VERSION 5.8 ;
BUSBITCHARS "[]" ;
DIVIDERCHAR "/" ;
UNITS
    DATABASE MICRONS 1000 ;
END UNITS

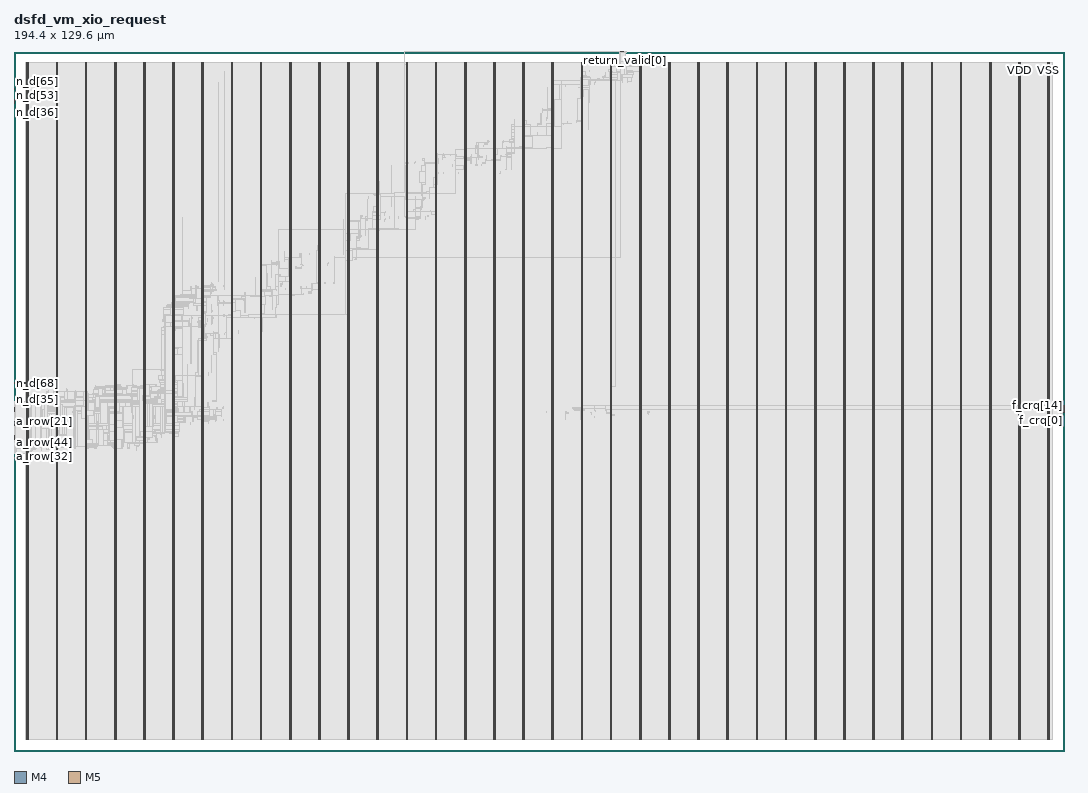
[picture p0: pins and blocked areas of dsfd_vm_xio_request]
MACRO dsfd_vm_xio_request
  FOREIGN dsfd_vm_xio_request 0 0 ;
  CLASS BLOCK ;
  SIZE 194.4 BY 129.6 ;
  PIN a_row[0]
    DIRECTION OUTPUT ;
    USE SIGNAL ;
    PORT
      LAYER M4 ;
        RECT  0 58.992 0.084 59.016 ;
    END
  END a_row[0]
  PIN a_row[10]
    DIRECTION OUTPUT ;
    USE SIGNAL ;
    PORT
      LAYER M4 ;
        RECT  0 59.952 0.084 59.976 ;
    END
  END a_row[10]
  PIN a_row[11]
    DIRECTION OUTPUT ;
    USE SIGNAL ;
    PORT
      LAYER M4 ;
        RECT  0 60.048 0.084 60.072 ;
    END
  END a_row[11]
  PIN a_row[12]
    DIRECTION OUTPUT ;
    USE SIGNAL ;
    PORT
      LAYER M4 ;
        RECT  0 60.144 0.084 60.168 ;
    END
  END a_row[12]
  PIN a_row[13]
    DIRECTION OUTPUT ;
    USE SIGNAL ;
    PORT
      LAYER M4 ;
        RECT  0 60.24 0.084 60.264 ;
    END
  END a_row[13]
  PIN a_row[14]
    DIRECTION OUTPUT ;
    USE SIGNAL ;
    PORT
      LAYER M4 ;
        RECT  0 60.336 0.084 60.36 ;
    END
  END a_row[14]
  PIN a_row[15]
    DIRECTION OUTPUT ;
    USE SIGNAL ;
    PORT
      LAYER M4 ;
        RECT  0 60.432 0.084 60.456 ;
    END
  END a_row[15]
  PIN a_row[16]
    DIRECTION OUTPUT ;
    USE SIGNAL ;
    PORT
      LAYER M4 ;
        RECT  0 60.528 0.084 60.552 ;
    END
  END a_row[16]
  PIN a_row[17]
    DIRECTION OUTPUT ;
    USE SIGNAL ;
    PORT
      LAYER M4 ;
        RECT  0 60.624 0.084 60.648 ;
    END
  END a_row[17]
  PIN a_row[18]
    DIRECTION OUTPUT ;
    USE SIGNAL ;
    PORT
      LAYER M4 ;
        RECT  0 60.72 0.084 60.744 ;
    END
  END a_row[18]
  PIN a_row[19]
    DIRECTION OUTPUT ;
    USE SIGNAL ;
    PORT
      LAYER M4 ;
        RECT  0 60.816 0.084 60.84 ;
    END
  END a_row[19]
  PIN a_row[1]
    DIRECTION OUTPUT ;
    USE SIGNAL ;
    PORT
      LAYER M4 ;
        RECT  0 59.088 0.084 59.112 ;
    END
  END a_row[1]
  PIN a_row[20]
    DIRECTION OUTPUT ;
    USE SIGNAL ;
    PORT
      LAYER M4 ;
        RECT  0 60.912 0.084 60.936 ;
    END
  END a_row[20]
  PIN a_row[21]
    DIRECTION OUTPUT ;
    USE SIGNAL ;
    PORT
      LAYER M4 ;
        RECT  0 61.008 0.084 61.032 ;
    END
  END a_row[21]
  PIN a_row[22]
    DIRECTION OUTPUT ;
    USE SIGNAL ;
    PORT
      LAYER M4 ;
        RECT  0 61.104 0.084 61.128 ;
    END
  END a_row[22]
  PIN a_row[23]
    DIRECTION OUTPUT ;
    USE SIGNAL ;
    PORT
      LAYER M4 ;
        RECT  0 61.2 0.084 61.224 ;
    END
  END a_row[23]
  PIN a_row[24]
    DIRECTION OUTPUT ;
    USE SIGNAL ;
    PORT
      LAYER M4 ;
        RECT  0 61.296 0.084 61.32 ;
    END
  END a_row[24]
  PIN a_row[25]
    DIRECTION OUTPUT ;
    USE SIGNAL ;
    PORT
      LAYER M4 ;
        RECT  0 61.392 0.084 61.416 ;
    END
  END a_row[25]
  PIN a_row[26]
    DIRECTION OUTPUT ;
    USE SIGNAL ;
    PORT
      LAYER M4 ;
        RECT  0 61.488 0.084 61.512 ;
    END
  END a_row[26]
  PIN a_row[27]
    DIRECTION OUTPUT ;
    USE SIGNAL ;
    PORT
      LAYER M4 ;
        RECT  0 61.584 0.084 61.608 ;
    END
  END a_row[27]
  PIN a_row[28]
    DIRECTION OUTPUT ;
    USE SIGNAL ;
    PORT
      LAYER M4 ;
        RECT  0 61.68 0.084 61.704 ;
    END
  END a_row[28]
  PIN a_row[29]
    DIRECTION OUTPUT ;
    USE SIGNAL ;
    PORT
      LAYER M4 ;
        RECT  0 61.776 0.084 61.8 ;
    END
  END a_row[29]
  PIN a_row[2]
    DIRECTION OUTPUT ;
    USE SIGNAL ;
    PORT
      LAYER M4 ;
        RECT  0 59.184 0.084 59.208 ;
    END
  END a_row[2]
  PIN a_row[30]
    DIRECTION OUTPUT ;
    USE SIGNAL ;
    PORT
      LAYER M4 ;
        RECT  0 61.872 0.084 61.896 ;
    END
  END a_row[30]
  PIN a_row[31]
    DIRECTION OUTPUT ;
    USE SIGNAL ;
    PORT
      LAYER M4 ;
        RECT  0 61.968 0.084 61.992 ;
    END
  END a_row[31]
  PIN a_row[32]
    DIRECTION OUTPUT ;
    USE SIGNAL ;
    PORT
      LAYER M4 ;
        RECT  0 55.92 0.084 55.944 ;
    END
  END a_row[32]
  PIN a_row[33]
    DIRECTION OUTPUT ;
    USE SIGNAL ;
    PORT
      LAYER M4 ;
        RECT  0 56.016 0.084 56.04 ;
    END
  END a_row[33]
  PIN a_row[34]
    DIRECTION OUTPUT ;
    USE SIGNAL ;
    PORT
      LAYER M4 ;
        RECT  0 56.112 0.084 56.136 ;
    END
  END a_row[34]
  PIN a_row[35]
    DIRECTION OUTPUT ;
    USE SIGNAL ;
    PORT
      LAYER M4 ;
        RECT  0 56.208 0.084 56.232 ;
    END
  END a_row[35]
  PIN a_row[36]
    DIRECTION OUTPUT ;
    USE SIGNAL ;
    PORT
      LAYER M4 ;
        RECT  0 56.304 0.084 56.328 ;
    END
  END a_row[36]
  PIN a_row[37]
    DIRECTION OUTPUT ;
    USE SIGNAL ;
    PORT
      LAYER M4 ;
        RECT  0 56.4 0.084 56.424 ;
    END
  END a_row[37]
  PIN a_row[38]
    DIRECTION OUTPUT ;
    USE SIGNAL ;
    PORT
      LAYER M4 ;
        RECT  0 56.496 0.084 56.52 ;
    END
  END a_row[38]
  PIN a_row[39]
    DIRECTION OUTPUT ;
    USE SIGNAL ;
    PORT
      LAYER M4 ;
        RECT  0 56.592 0.084 56.616 ;
    END
  END a_row[39]
  PIN a_row[3]
    DIRECTION OUTPUT ;
    USE SIGNAL ;
    PORT
      LAYER M4 ;
        RECT  0 59.28 0.084 59.304 ;
    END
  END a_row[3]
  PIN a_row[40]
    DIRECTION OUTPUT ;
    USE SIGNAL ;
    PORT
      LAYER M4 ;
        RECT  0 56.688 0.084 56.712 ;
    END
  END a_row[40]
  PIN a_row[41]
    DIRECTION OUTPUT ;
    USE SIGNAL ;
    PORT
      LAYER M4 ;
        RECT  0 56.784 0.084 56.808 ;
    END
  END a_row[41]
  PIN a_row[42]
    DIRECTION OUTPUT ;
    USE SIGNAL ;
    PORT
      LAYER M4 ;
        RECT  0 56.88 0.084 56.904 ;
    END
  END a_row[42]
  PIN a_row[43]
    DIRECTION OUTPUT ;
    USE SIGNAL ;
    PORT
      LAYER M4 ;
        RECT  0 56.976 0.084 57 ;
    END
  END a_row[43]
  PIN a_row[44]
    DIRECTION OUTPUT ;
    USE SIGNAL ;
    PORT
      LAYER M4 ;
        RECT  0 57.072 0.084 57.096 ;
    END
  END a_row[44]
  PIN a_row[45]
    DIRECTION OUTPUT ;
    USE SIGNAL ;
    PORT
      LAYER M4 ;
        RECT  0 57.168 0.084 57.192 ;
    END
  END a_row[45]
  PIN a_row[46]
    DIRECTION OUTPUT ;
    USE SIGNAL ;
    PORT
      LAYER M4 ;
        RECT  0 57.264 0.084 57.288 ;
    END
  END a_row[46]
  PIN a_row[47]
    DIRECTION OUTPUT ;
    USE SIGNAL ;
    PORT
      LAYER M4 ;
        RECT  0 57.36 0.084 57.384 ;
    END
  END a_row[47]
  PIN a_row[48]
    DIRECTION OUTPUT ;
    USE SIGNAL ;
    PORT
      LAYER M4 ;
        RECT  0 57.456 0.084 57.48 ;
    END
  END a_row[48]
  PIN a_row[49]
    DIRECTION OUTPUT ;
    USE SIGNAL ;
    PORT
      LAYER M4 ;
        RECT  0 57.552 0.084 57.576 ;
    END
  END a_row[49]
  PIN a_row[4]
    DIRECTION OUTPUT ;
    USE SIGNAL ;
    PORT
      LAYER M4 ;
        RECT  0 59.376 0.084 59.4 ;
    END
  END a_row[4]
  PIN a_row[50]
    DIRECTION OUTPUT ;
    USE SIGNAL ;
    PORT
      LAYER M4 ;
        RECT  0 57.648 0.084 57.672 ;
    END
  END a_row[50]
  PIN a_row[51]
    DIRECTION OUTPUT ;
    USE SIGNAL ;
    PORT
      LAYER M4 ;
        RECT  0 57.744 0.084 57.768 ;
    END
  END a_row[51]
  PIN a_row[52]
    DIRECTION OUTPUT ;
    USE SIGNAL ;
    PORT
      LAYER M4 ;
        RECT  0 57.84 0.084 57.864 ;
    END
  END a_row[52]
  PIN a_row[53]
    DIRECTION OUTPUT ;
    USE SIGNAL ;
    PORT
      LAYER M4 ;
        RECT  0 57.936 0.084 57.96 ;
    END
  END a_row[53]
  PIN a_row[54]
    DIRECTION OUTPUT ;
    USE SIGNAL ;
    PORT
      LAYER M4 ;
        RECT  0 58.032 0.084 58.056 ;
    END
  END a_row[54]
  PIN a_row[55]
    DIRECTION OUTPUT ;
    USE SIGNAL ;
    PORT
      LAYER M4 ;
        RECT  0 58.128 0.084 58.152 ;
    END
  END a_row[55]
  PIN a_row[5]
    DIRECTION OUTPUT ;
    USE SIGNAL ;
    PORT
      LAYER M4 ;
        RECT  0 59.472 0.084 59.496 ;
    END
  END a_row[5]
  PIN a_row[6]
    DIRECTION OUTPUT ;
    USE SIGNAL ;
    PORT
      LAYER M4 ;
        RECT  0 59.568 0.084 59.592 ;
    END
  END a_row[6]
  PIN a_row[7]
    DIRECTION OUTPUT ;
    USE SIGNAL ;
    PORT
      LAYER M4 ;
        RECT  0 59.664 0.084 59.688 ;
    END
  END a_row[7]
  PIN a_row[8]
    DIRECTION OUTPUT ;
    USE SIGNAL ;
    PORT
      LAYER M4 ;
        RECT  0 59.76 0.084 59.784 ;
    END
  END a_row[8]
  PIN a_row[9]
    DIRECTION OUTPUT ;
    USE SIGNAL ;
    PORT
      LAYER M4 ;
        RECT  0 59.856 0.084 59.88 ;
    END
  END a_row[9]
  PIN a_v[0]
    DIRECTION OUTPUT ;
    USE SIGNAL ;
    PORT
      LAYER M4 ;
        RECT  0 58.224 0.084 58.248 ;
    END
  END a_v[0]
  PIN a_v[1]
    DIRECTION OUTPUT ;
    USE SIGNAL ;
    PORT
      LAYER M4 ;
        RECT  0 58.32 0.084 58.344 ;
    END
  END a_v[1]
  PIN a_v[2]
    DIRECTION OUTPUT ;
    USE SIGNAL ;
    PORT
      LAYER M4 ;
        RECT  0 58.416 0.084 58.44 ;
    END
  END a_v[2]
  PIN a_v[3]
    DIRECTION OUTPUT ;
    USE SIGNAL ;
    PORT
      LAYER M4 ;
        RECT  0 58.512 0.084 58.536 ;
    END
  END a_v[3]
  PIN ck
    DIRECTION INPUT ;
    USE SIGNAL ;
    PORT
      LAYER M5 ;
        RECT  112.272 129.516 112.296 129.6 ;
    END
  END ck
  PIN f_crq[0]
    DIRECTION INPUT ;
    USE SIGNAL ;
    PORT
      LAYER M4 ;
        RECT  194.316 62.64 194.4 62.664 ;
    END
  END f_crq[0]
  PIN f_crq[10]
    DIRECTION INPUT ;
    USE SIGNAL ;
    PORT
      LAYER M4 ;
        RECT  194.316 63.6 194.4 63.624 ;
    END
  END f_crq[10]
  PIN f_crq[11]
    DIRECTION INPUT ;
    USE SIGNAL ;
    PORT
      LAYER M4 ;
        RECT  194.316 63.696 194.4 63.72 ;
    END
  END f_crq[11]
  PIN f_crq[12]
    DIRECTION INPUT ;
    USE SIGNAL ;
    PORT
      LAYER M4 ;
        RECT  194.316 63.792 194.4 63.816 ;
    END
  END f_crq[12]
  PIN f_crq[13]
    DIRECTION INPUT ;
    USE SIGNAL ;
    PORT
      LAYER M4 ;
        RECT  194.316 63.888 194.4 63.912 ;
    END
  END f_crq[13]
  PIN f_crq[14]
    DIRECTION INPUT ;
    USE SIGNAL ;
    PORT
      LAYER M4 ;
        RECT  194.316 63.984 194.4 64.008 ;
    END
  END f_crq[14]
  PIN f_crq[1]
    DIRECTION INPUT ;
    USE SIGNAL ;
    PORT
      LAYER M4 ;
        RECT  194.316 62.736 194.4 62.76 ;
    END
  END f_crq[1]
  PIN f_crq[2]
    DIRECTION INPUT ;
    USE SIGNAL ;
    PORT
      LAYER M4 ;
        RECT  194.316 62.832 194.4 62.856 ;
    END
  END f_crq[2]
  PIN f_crq[3]
    DIRECTION INPUT ;
    USE SIGNAL ;
    PORT
      LAYER M4 ;
        RECT  194.316 62.928 194.4 62.952 ;
    END
  END f_crq[3]
  PIN f_crq[4]
    DIRECTION INPUT ;
    USE SIGNAL ;
    PORT
      LAYER M4 ;
        RECT  194.316 63.024 194.4 63.048 ;
    END
  END f_crq[4]
  PIN f_crq[5]
    DIRECTION INPUT ;
    USE SIGNAL ;
    PORT
      LAYER M4 ;
        RECT  194.316 63.12 194.4 63.144 ;
    END
  END f_crq[5]
  PIN f_crq[6]
    DIRECTION INPUT ;
    USE SIGNAL ;
    PORT
      LAYER M4 ;
        RECT  194.316 63.216 194.4 63.24 ;
    END
  END f_crq[6]
  PIN f_crq[7]
    DIRECTION INPUT ;
    USE SIGNAL ;
    PORT
      LAYER M4 ;
        RECT  194.316 63.312 194.4 63.336 ;
    END
  END f_crq[7]
  PIN f_crq[8]
    DIRECTION INPUT ;
    USE SIGNAL ;
    PORT
      LAYER M4 ;
        RECT  194.316 63.408 194.4 63.432 ;
    END
  END f_crq[8]
  PIN f_crq[9]
    DIRECTION INPUT ;
    USE SIGNAL ;
    PORT
      LAYER M4 ;
        RECT  194.316 63.504 194.4 63.528 ;
    END
  END f_crq[9]
  PIN fault
    DIRECTION OUTPUT ;
    USE SIGNAL ;
    PORT
      LAYER M5 ;
        RECT  112.368 129.516 112.392 129.6 ;
    END
  END fault
  PIN n_d[0]
    DIRECTION INPUT ;
    USE SIGNAL ;
    PORT
      LAYER M4 ;
        RECT  0 58.608 0.084 58.632 ;
    END
  END n_d[0]
  PIN n_d[10]
    DIRECTION INPUT ;
    USE SIGNAL ;
    PORT
      LAYER M4 ;
        RECT  0 62.64 0.084 62.664 ;
    END
  END n_d[10]
  PIN n_d[11]
    DIRECTION INPUT ;
    USE SIGNAL ;
    PORT
      LAYER M4 ;
        RECT  0 62.736 0.084 62.76 ;
    END
  END n_d[11]
  PIN n_d[12]
    DIRECTION INPUT ;
    USE SIGNAL ;
    PORT
      LAYER M4 ;
        RECT  0 62.832 0.084 62.856 ;
    END
  END n_d[12]
  PIN n_d[13]
    DIRECTION INPUT ;
    USE SIGNAL ;
    PORT
      LAYER M4 ;
        RECT  0 62.928 0.084 62.952 ;
    END
  END n_d[13]
  PIN n_d[14]
    DIRECTION INPUT ;
    USE SIGNAL ;
    PORT
      LAYER M4 ;
        RECT  0 63.024 0.084 63.048 ;
    END
  END n_d[14]
  PIN n_d[15]
    DIRECTION INPUT ;
    USE SIGNAL ;
    PORT
      LAYER M4 ;
        RECT  0 63.12 0.084 63.144 ;
    END
  END n_d[15]
  PIN n_d[16]
    DIRECTION INPUT ;
    USE SIGNAL ;
    PORT
      LAYER M4 ;
        RECT  0 63.216 0.084 63.24 ;
    END
  END n_d[16]
  PIN n_d[17]
    DIRECTION INPUT ;
    USE SIGNAL ;
    PORT
      LAYER M4 ;
        RECT  0 63.312 0.084 63.336 ;
    END
  END n_d[17]
  PIN n_d[18]
    DIRECTION INPUT ;
    USE SIGNAL ;
    PORT
      LAYER M4 ;
        RECT  0 63.408 0.084 63.432 ;
    END
  END n_d[18]
  PIN n_d[19]
    DIRECTION INPUT ;
    USE SIGNAL ;
    PORT
      LAYER M4 ;
        RECT  0 63.504 0.084 63.528 ;
    END
  END n_d[19]
  PIN n_d[1]
    DIRECTION INPUT ;
    USE SIGNAL ;
    PORT
      LAYER M4 ;
        RECT  0 58.704 0.084 58.728 ;
    END
  END n_d[1]
  PIN n_d[20]
    DIRECTION INPUT ;
    USE SIGNAL ;
    PORT
      LAYER M4 ;
        RECT  0 63.6 0.084 63.624 ;
    END
  END n_d[20]
  PIN n_d[21]
    DIRECTION INPUT ;
    USE SIGNAL ;
    PORT
      LAYER M4 ;
        RECT  0 63.696 0.084 63.72 ;
    END
  END n_d[21]
  PIN n_d[22]
    DIRECTION INPUT ;
    USE SIGNAL ;
    PORT
      LAYER M4 ;
        RECT  0 63.792 0.084 63.816 ;
    END
  END n_d[22]
  PIN n_d[23]
    DIRECTION INPUT ;
    USE SIGNAL ;
    PORT
      LAYER M4 ;
        RECT  0 63.888 0.084 63.912 ;
    END
  END n_d[23]
  PIN n_d[24]
    DIRECTION INPUT ;
    USE SIGNAL ;
    PORT
      LAYER M4 ;
        RECT  0 63.984 0.084 64.008 ;
    END
  END n_d[24]
  PIN n_d[25]
    DIRECTION INPUT ;
    USE SIGNAL ;
    PORT
      LAYER M4 ;
        RECT  0 64.08 0.084 64.104 ;
    END
  END n_d[25]
  PIN n_d[26]
    DIRECTION INPUT ;
    USE SIGNAL ;
    PORT
      LAYER M4 ;
        RECT  0 64.176 0.084 64.2 ;
    END
  END n_d[26]
  PIN n_d[27]
    DIRECTION INPUT ;
    USE SIGNAL ;
    PORT
      LAYER M4 ;
        RECT  0 64.272 0.084 64.296 ;
    END
  END n_d[27]
  PIN n_d[28]
    DIRECTION INPUT ;
    USE SIGNAL ;
    PORT
      LAYER M4 ;
        RECT  0 64.368 0.084 64.392 ;
    END
  END n_d[28]
  PIN n_d[29]
    DIRECTION INPUT ;
    USE SIGNAL ;
    PORT
      LAYER M4 ;
        RECT  0 64.464 0.084 64.488 ;
    END
  END n_d[29]
  PIN n_d[2]
    DIRECTION INPUT ;
    USE SIGNAL ;
    PORT
      LAYER M4 ;
        RECT  0 58.8 0.084 58.824 ;
    END
  END n_d[2]
  PIN n_d[30]
    DIRECTION INPUT ;
    USE SIGNAL ;
    PORT
      LAYER M4 ;
        RECT  0 64.56 0.084 64.584 ;
    END
  END n_d[30]
  PIN n_d[31]
    DIRECTION INPUT ;
    USE SIGNAL ;
    PORT
      LAYER M4 ;
        RECT  0 64.656 0.084 64.68 ;
    END
  END n_d[31]
  PIN n_d[32]
    DIRECTION INPUT ;
    USE SIGNAL ;
    PORT
      LAYER M4 ;
        RECT  0 64.752 0.084 64.776 ;
    END
  END n_d[32]
  PIN n_d[33]
    DIRECTION INPUT ;
    USE SIGNAL ;
    PORT
      LAYER M4 ;
        RECT  0 64.848 0.084 64.872 ;
    END
  END n_d[33]
  PIN n_d[34]
    DIRECTION INPUT ;
    USE SIGNAL ;
    PORT
      LAYER M4 ;
        RECT  0 64.944 0.084 64.968 ;
    END
  END n_d[34]
  PIN n_d[35]
    DIRECTION INPUT ;
    USE SIGNAL ;
    PORT
      LAYER M4 ;
        RECT  0 65.04 0.084 65.064 ;
    END
  END n_d[35]
  PIN n_d[36]
    DIRECTION INPUT ;
    USE SIGNAL ;
    PORT
      LAYER M4 ;
        RECT  0 119.664 0.084 119.688 ;
    END
  END n_d[36]
  PIN n_d[37]
    DIRECTION INPUT ;
    USE SIGNAL ;
    PORT
      LAYER M4 ;
        RECT  0 119.76 0.084 119.784 ;
    END
  END n_d[37]
  PIN n_d[38]
    DIRECTION INPUT ;
    USE SIGNAL ;
    PORT
      LAYER M4 ;
        RECT  0 119.856 0.084 119.88 ;
    END
  END n_d[38]
  PIN n_d[39]
    DIRECTION INPUT ;
    USE SIGNAL ;
    PORT
      LAYER M4 ;
        RECT  0 119.952 0.084 119.976 ;
    END
  END n_d[39]
  PIN n_d[3]
    DIRECTION INPUT ;
    USE SIGNAL ;
    PORT
      LAYER M4 ;
        RECT  0 58.896 0.084 58.92 ;
    END
  END n_d[3]
  PIN n_d[40]
    DIRECTION INPUT ;
    USE SIGNAL ;
    PORT
      LAYER M4 ;
        RECT  0 120.048 0.084 120.072 ;
    END
  END n_d[40]
  PIN n_d[41]
    DIRECTION INPUT ;
    USE SIGNAL ;
    PORT
      LAYER M4 ;
        RECT  0 120.144 0.084 120.168 ;
    END
  END n_d[41]
  PIN n_d[42]
    DIRECTION INPUT ;
    USE SIGNAL ;
    PORT
      LAYER M4 ;
        RECT  0 120.24 0.084 120.264 ;
    END
  END n_d[42]
  PIN n_d[43]
    DIRECTION INPUT ;
    USE SIGNAL ;
    PORT
      LAYER M4 ;
        RECT  0 120.336 0.084 120.36 ;
    END
  END n_d[43]
  PIN n_d[44]
    DIRECTION INPUT ;
    USE SIGNAL ;
    PORT
      LAYER M4 ;
        RECT  0 120.432 0.084 120.456 ;
    END
  END n_d[44]
  PIN n_d[45]
    DIRECTION INPUT ;
    USE SIGNAL ;
    PORT
      LAYER M4 ;
        RECT  0 120.528 0.084 120.552 ;
    END
  END n_d[45]
  PIN n_d[46]
    DIRECTION INPUT ;
    USE SIGNAL ;
    PORT
      LAYER M4 ;
        RECT  0 120.624 0.084 120.648 ;
    END
  END n_d[46]
  PIN n_d[47]
    DIRECTION INPUT ;
    USE SIGNAL ;
    PORT
      LAYER M4 ;
        RECT  0 120.72 0.084 120.744 ;
    END
  END n_d[47]
  PIN n_d[48]
    DIRECTION INPUT ;
    USE SIGNAL ;
    PORT
      LAYER M4 ;
        RECT  0 120.816 0.084 120.84 ;
    END
  END n_d[48]
  PIN n_d[49]
    DIRECTION INPUT ;
    USE SIGNAL ;
    PORT
      LAYER M4 ;
        RECT  0 120.912 0.084 120.936 ;
    END
  END n_d[49]
  PIN n_d[4]
    DIRECTION INPUT ;
    USE SIGNAL ;
    PORT
      LAYER M4 ;
        RECT  0 62.064 0.084 62.088 ;
    END
  END n_d[4]
  PIN n_d[50]
    DIRECTION INPUT ;
    USE SIGNAL ;
    PORT
      LAYER M4 ;
        RECT  0 121.008 0.084 121.032 ;
    END
  END n_d[50]
  PIN n_d[51]
    DIRECTION INPUT ;
    USE SIGNAL ;
    PORT
      LAYER M4 ;
        RECT  0 121.104 0.084 121.128 ;
    END
  END n_d[51]
  PIN n_d[52]
    DIRECTION INPUT ;
    USE SIGNAL ;
    PORT
      LAYER M4 ;
        RECT  0 121.2 0.084 121.224 ;
    END
  END n_d[52]
  PIN n_d[53]
    DIRECTION INPUT ;
    USE SIGNAL ;
    PORT
      LAYER M4 ;
        RECT  0 121.296 0.084 121.32 ;
    END
  END n_d[53]
  PIN n_d[54]
    DIRECTION INPUT ;
    USE SIGNAL ;
    PORT
      LAYER M4 ;
        RECT  0 121.392 0.084 121.416 ;
    END
  END n_d[54]
  PIN n_d[55]
    DIRECTION INPUT ;
    USE SIGNAL ;
    PORT
      LAYER M4 ;
        RECT  0 121.488 0.084 121.512 ;
    END
  END n_d[55]
  PIN n_d[56]
    DIRECTION INPUT ;
    USE SIGNAL ;
    PORT
      LAYER M4 ;
        RECT  0 121.584 0.084 121.608 ;
    END
  END n_d[56]
  PIN n_d[57]
    DIRECTION INPUT ;
    USE SIGNAL ;
    PORT
      LAYER M4 ;
        RECT  0 121.68 0.084 121.704 ;
    END
  END n_d[57]
  PIN n_d[58]
    DIRECTION INPUT ;
    USE SIGNAL ;
    PORT
      LAYER M4 ;
        RECT  0 121.776 0.084 121.8 ;
    END
  END n_d[58]
  PIN n_d[59]
    DIRECTION INPUT ;
    USE SIGNAL ;
    PORT
      LAYER M4 ;
        RECT  0 121.872 0.084 121.896 ;
    END
  END n_d[59]
  PIN n_d[5]
    DIRECTION INPUT ;
    USE SIGNAL ;
    PORT
      LAYER M4 ;
        RECT  0 62.16 0.084 62.184 ;
    END
  END n_d[5]
  PIN n_d[60]
    DIRECTION INPUT ;
    USE SIGNAL ;
    PORT
      LAYER M4 ;
        RECT  0 121.968 0.084 121.992 ;
    END
  END n_d[60]
  PIN n_d[61]
    DIRECTION INPUT ;
    USE SIGNAL ;
    PORT
      LAYER M4 ;
        RECT  0 122.064 0.084 122.088 ;
    END
  END n_d[61]
  PIN n_d[62]
    DIRECTION INPUT ;
    USE SIGNAL ;
    PORT
      LAYER M4 ;
        RECT  0 122.16 0.084 122.184 ;
    END
  END n_d[62]
  PIN n_d[63]
    DIRECTION INPUT ;
    USE SIGNAL ;
    PORT
      LAYER M4 ;
        RECT  0 122.256 0.084 122.28 ;
    END
  END n_d[63]
  PIN n_d[64]
    DIRECTION INPUT ;
    USE SIGNAL ;
    PORT
      LAYER M4 ;
        RECT  0 122.352 0.084 122.376 ;
    END
  END n_d[64]
  PIN n_d[65]
    DIRECTION INPUT ;
    USE SIGNAL ;
    PORT
      LAYER M4 ;
        RECT  0 122.448 0.084 122.472 ;
    END
  END n_d[65]
  PIN n_d[66]
    DIRECTION INPUT ;
    USE SIGNAL ;
    PORT
      LAYER M4 ;
        RECT  0 122.544 0.084 122.568 ;
    END
  END n_d[66]
  PIN n_d[67]
    DIRECTION INPUT ;
    USE SIGNAL ;
    PORT
      LAYER M4 ;
        RECT  0 122.64 0.084 122.664 ;
    END
  END n_d[67]
  PIN n_d[68]
    DIRECTION INPUT ;
    USE SIGNAL ;
    PORT
      LAYER M4 ;
        RECT  0 66.576 0.084 66.6 ;
    END
  END n_d[68]
  PIN n_d[69]
    DIRECTION INPUT ;
    USE SIGNAL ;
    PORT
      LAYER M4 ;
        RECT  0 66.672 0.084 66.696 ;
    END
  END n_d[69]
  PIN n_d[6]
    DIRECTION INPUT ;
    USE SIGNAL ;
    PORT
      LAYER M4 ;
        RECT  0 62.256 0.084 62.28 ;
    END
  END n_d[6]
  PIN n_d[70]
    DIRECTION INPUT ;
    USE SIGNAL ;
    PORT
      LAYER M4 ;
        RECT  0 66.768 0.084 66.792 ;
    END
  END n_d[70]
  PIN n_d[71]
    DIRECTION INPUT ;
    USE SIGNAL ;
    PORT
      LAYER M4 ;
        RECT  0 66.864 0.084 66.888 ;
    END
  END n_d[71]
  PIN n_d[72]
    DIRECTION INPUT ;
    USE SIGNAL ;
    PORT
      LAYER M4 ;
        RECT  0 66.96 0.084 66.984 ;
    END
  END n_d[72]
  PIN n_d[73]
    DIRECTION INPUT ;
    USE SIGNAL ;
    PORT
      LAYER M4 ;
        RECT  0 67.056 0.084 67.08 ;
    END
  END n_d[73]
  PIN n_d[74]
    DIRECTION INPUT ;
    USE SIGNAL ;
    PORT
      LAYER M4 ;
        RECT  0 67.152 0.084 67.176 ;
    END
  END n_d[74]
  PIN n_d[75]
    DIRECTION INPUT ;
    USE SIGNAL ;
    PORT
      LAYER M4 ;
        RECT  0 67.248 0.084 67.272 ;
    END
  END n_d[75]
  PIN n_d[76]
    DIRECTION INPUT ;
    USE SIGNAL ;
    PORT
      LAYER M4 ;
        RECT  0 67.344 0.084 67.368 ;
    END
  END n_d[76]
  PIN n_d[77]
    DIRECTION INPUT ;
    USE SIGNAL ;
    PORT
      LAYER M4 ;
        RECT  0 67.44 0.084 67.464 ;
    END
  END n_d[77]
  PIN n_d[78]
    DIRECTION INPUT ;
    USE SIGNAL ;
    PORT
      LAYER M4 ;
        RECT  0 67.536 0.084 67.56 ;
    END
  END n_d[78]
  PIN n_d[79]
    DIRECTION INPUT ;
    USE SIGNAL ;
    PORT
      LAYER M4 ;
        RECT  0 67.632 0.084 67.656 ;
    END
  END n_d[79]
  PIN n_d[7]
    DIRECTION INPUT ;
    USE SIGNAL ;
    PORT
      LAYER M4 ;
        RECT  0 62.352 0.084 62.376 ;
    END
  END n_d[7]
  PIN n_d[80]
    DIRECTION INPUT ;
    USE SIGNAL ;
    PORT
      LAYER M4 ;
        RECT  0 67.728 0.084 67.752 ;
    END
  END n_d[80]
  PIN n_d[81]
    DIRECTION INPUT ;
    USE SIGNAL ;
    PORT
      LAYER M4 ;
        RECT  0 67.824 0.084 67.848 ;
    END
  END n_d[81]
  PIN n_d[82]
    DIRECTION INPUT ;
    USE SIGNAL ;
    PORT
      LAYER M4 ;
        RECT  0 67.92 0.084 67.944 ;
    END
  END n_d[82]
  PIN n_d[83]
    DIRECTION INPUT ;
    USE SIGNAL ;
    PORT
      LAYER M4 ;
        RECT  0 68.016 0.084 68.04 ;
    END
  END n_d[83]
  PIN n_d[8]
    DIRECTION INPUT ;
    USE SIGNAL ;
    PORT
      LAYER M4 ;
        RECT  0 62.448 0.084 62.472 ;
    END
  END n_d[8]
  PIN n_d[9]
    DIRECTION INPUT ;
    USE SIGNAL ;
    PORT
      LAYER M4 ;
        RECT  0 62.544 0.084 62.568 ;
    END
  END n_d[9]
  PIN n_v
    DIRECTION INPUT ;
    USE SIGNAL ;
    PORT
      LAYER M4 ;
        RECT  0 68.112 0.084 68.136 ;
    END
    PORT
      LAYER M4 ;
        RECT  0.06 68.112 2.408 68.136 ;
    END
  END n_v
  PIN return_lane[0]
    DIRECTION OUTPUT ;
    USE SIGNAL ;
    PORT
      LAYER M5 ;
        RECT  112.464 129.516 112.488 129.6 ;
    END
  END return_lane[0]
  PIN return_lane[1]
    DIRECTION OUTPUT ;
    USE SIGNAL ;
    PORT
      LAYER M5 ;
        RECT  112.56 129.516 112.584 129.6 ;
    END
  END return_lane[1]
  PIN return_lane[2]
    DIRECTION OUTPUT ;
    USE SIGNAL ;
    PORT
      LAYER M5 ;
        RECT  112.656 129.516 112.68 129.6 ;
    END
  END return_lane[2]
  PIN return_lane[3]
    DIRECTION OUTPUT ;
    USE SIGNAL ;
    PORT
      LAYER M5 ;
        RECT  112.752 129.516 112.776 129.6 ;
    END
  END return_lane[3]
  PIN return_lane[4]
    DIRECTION OUTPUT ;
    USE SIGNAL ;
    PORT
      LAYER M5 ;
        RECT  112.848 129.516 112.872 129.6 ;
    END
  END return_lane[4]
  PIN return_lane[5]
    DIRECTION OUTPUT ;
    USE SIGNAL ;
    PORT
      LAYER M5 ;
        RECT  112.944 129.516 112.968 129.6 ;
    END
  END return_lane[5]
  PIN return_valid[0]
    DIRECTION OUTPUT ;
    USE SIGNAL ;
    PORT
      LAYER M5 ;
        RECT  113.04 129.516 113.064 129.6 ;
    END
  END return_valid[0]
  PIN return_valid[1]
    DIRECTION OUTPUT ;
    USE SIGNAL ;
    PORT
      LAYER M5 ;
        RECT  113.136 129.516 113.16 129.6 ;
    END
  END return_valid[1]
  PIN return_valid[2]
    DIRECTION OUTPUT ;
    USE SIGNAL ;
    PORT
      LAYER M5 ;
        RECT  113.232 129.516 113.256 129.6 ;
    END
  END return_valid[2]
  PIN rst_n
    DIRECTION INPUT ;
    USE SIGNAL ;
    PORT
      LAYER M5 ;
        RECT  113.328 129.516 113.352 129.6 ;
    END
  END rst_n
  PIN VDD
    DIRECTION INOUT ;
    USE POWER ;
    PORT
      LAYER M5 ;
        RECT  191.592 2.151 191.712 127.449 ;
        RECT  186.192 2.151 186.312 127.449 ;
        RECT  180.792 2.151 180.912 127.449 ;
        RECT  175.392 2.151 175.512 127.449 ;
        RECT  169.992 2.151 170.112 127.449 ;
        RECT  164.592 2.151 164.712 127.449 ;
        RECT  159.192 2.151 159.312 127.449 ;
        RECT  153.792 2.151 153.912 127.449 ;
        RECT  148.392 2.151 148.512 127.449 ;
        RECT  142.992 2.151 143.112 127.449 ;
        RECT  137.592 2.151 137.712 127.449 ;
        RECT  132.192 2.151 132.312 127.449 ;
        RECT  126.792 2.151 126.912 127.449 ;
        RECT  121.392 2.151 121.512 127.449 ;
        RECT  115.992 2.151 116.112 127.449 ;
        RECT  110.592 2.151 110.712 127.449 ;
        RECT  105.192 2.151 105.312 127.449 ;
        RECT  99.792 2.151 99.912 127.449 ;
        RECT  94.392 2.151 94.512 127.449 ;
        RECT  88.992 2.151 89.112 127.449 ;
        RECT  83.592 2.151 83.712 127.449 ;
        RECT  78.192 2.151 78.312 127.449 ;
        RECT  72.792 2.151 72.912 127.449 ;
        RECT  67.392 2.151 67.512 127.449 ;
        RECT  61.992 2.151 62.112 127.449 ;
        RECT  56.592 2.151 56.712 127.449 ;
        RECT  51.192 2.151 51.312 127.449 ;
        RECT  45.792 2.151 45.912 127.449 ;
        RECT  40.392 2.151 40.512 127.449 ;
        RECT  34.992 2.151 35.112 127.449 ;
        RECT  29.592 2.151 29.712 127.449 ;
        RECT  24.192 2.151 24.312 127.449 ;
        RECT  18.792 2.151 18.912 127.449 ;
        RECT  13.392 2.151 13.512 127.449 ;
        RECT  7.992 2.151 8.112 127.449 ;
        RECT  2.592 2.151 2.712 127.449 ;
    END
  END VDD
  PIN VSS
    DIRECTION INOUT ;
    USE GROUND ;
    PORT
      LAYER M5 ;
        RECT  191.4 2.137 191.52 127.463 ;
        RECT  186 2.137 186.12 127.463 ;
        RECT  180.6 2.137 180.72 127.463 ;
        RECT  175.2 2.137 175.32 127.463 ;
        RECT  169.8 2.137 169.92 127.463 ;
        RECT  164.4 2.137 164.52 127.463 ;
        RECT  159 2.137 159.12 127.463 ;
        RECT  153.6 2.137 153.72 127.463 ;
        RECT  148.2 2.137 148.32 127.463 ;
        RECT  142.8 2.137 142.92 127.463 ;
        RECT  137.4 2.137 137.52 127.463 ;
        RECT  132 2.137 132.12 127.463 ;
        RECT  126.6 2.137 126.72 127.463 ;
        RECT  121.2 2.137 121.32 127.463 ;
        RECT  115.8 2.137 115.92 127.463 ;
        RECT  110.4 2.137 110.52 127.463 ;
        RECT  105 2.137 105.12 127.463 ;
        RECT  99.6 2.137 99.72 127.463 ;
        RECT  94.2 2.137 94.32 127.463 ;
        RECT  88.8 2.137 88.92 127.463 ;
        RECT  83.4 2.137 83.52 127.463 ;
        RECT  78 2.137 78.12 127.463 ;
        RECT  72.6 2.137 72.72 127.463 ;
        RECT  67.2 2.137 67.32 127.463 ;
        RECT  61.8 2.137 61.92 127.463 ;
        RECT  56.4 2.137 56.52 127.463 ;
        RECT  51 2.137 51.12 127.463 ;
        RECT  45.6 2.137 45.72 127.463 ;
        RECT  40.2 2.137 40.32 127.463 ;
        RECT  34.8 2.137 34.92 127.463 ;
        RECT  29.4 2.137 29.52 127.463 ;
        RECT  24 2.137 24.12 127.463 ;
        RECT  18.6 2.137 18.72 127.463 ;
        RECT  13.2 2.137 13.32 127.463 ;
        RECT  7.8 2.137 7.92 127.463 ;
        RECT  2.4 2.137 2.52 127.463 ;
    END
  END VSS
  # OT_OBS_CLOSED layer=M5 d_um=1.536 added=39
  OBS
    LAYER RVTN ;
     RECT  2.16 2.16 192.24 2.295 ;
     RECT  2.16 2.565 192.24 2.835 ;
     RECT  2.16 3.105 192.24 3.375 ;
     RECT  2.16 3.645 192.24 3.915 ;
     RECT  2.16 4.185 192.24 4.455 ;
     RECT  2.16 4.725 192.24 4.995 ;
     RECT  2.16 5.265 192.24 5.535 ;
     RECT  2.16 5.805 192.24 6.075 ;
     RECT  2.16 6.345 192.24 6.615 ;
     RECT  2.16 6.885 192.24 7.155 ;
     RECT  2.16 7.425 192.24 7.695 ;
     RECT  2.16 7.965 192.24 8.235 ;
     RECT  2.16 8.505 192.24 8.775 ;
     RECT  2.16 9.045 192.24 9.315 ;
     RECT  2.16 9.585 192.24 9.855 ;
     RECT  2.16 10.125 192.24 10.395 ;
     RECT  2.16 10.665 192.24 10.935 ;
     RECT  2.16 11.205 192.24 11.475 ;
     RECT  2.16 11.745 192.24 12.015 ;
     RECT  2.16 12.285 192.24 12.555 ;
     RECT  2.16 12.825 192.24 13.095 ;
     RECT  2.16 13.365 192.24 13.635 ;
     RECT  2.16 13.905 192.24 14.175 ;
     RECT  2.16 14.445 192.24 14.715 ;
     RECT  2.16 14.985 192.24 15.255 ;
     RECT  2.16 15.525 192.24 15.795 ;
     RECT  2.16 16.065 192.24 16.335 ;
     RECT  2.16 16.605 192.24 16.875 ;
     RECT  2.16 17.145 192.24 17.415 ;
     RECT  2.16 17.685 192.24 17.955 ;
     RECT  2.16 18.225 192.24 18.495 ;
     RECT  2.16 18.765 192.24 19.035 ;
     RECT  2.16 19.305 192.24 19.575 ;
     RECT  2.16 19.845 192.24 20.115 ;
     RECT  2.16 20.385 192.24 20.655 ;
     RECT  2.16 20.925 192.24 21.195 ;
     RECT  2.16 21.465 192.24 21.735 ;
     RECT  2.16 22.005 192.24 22.275 ;
     RECT  2.16 22.545 192.24 22.815 ;
     RECT  2.16 23.085 192.24 23.355 ;
     RECT  2.16 23.625 192.24 23.895 ;
     RECT  2.16 24.165 192.24 24.435 ;
     RECT  2.16 24.705 192.24 24.975 ;
     RECT  2.16 25.245 192.24 25.515 ;
     RECT  2.16 25.785 192.24 26.055 ;
     RECT  2.16 26.325 192.24 26.595 ;
     RECT  2.16 26.865 192.24 27.135 ;
     RECT  2.16 27.405 192.24 27.675 ;
     RECT  2.16 27.945 192.24 28.215 ;
     RECT  2.16 28.485 192.24 28.755 ;
     RECT  2.16 29.025 192.24 29.295 ;
     RECT  2.16 29.565 192.24 29.835 ;
     RECT  2.16 30.105 192.24 30.375 ;
     RECT  2.16 30.645 192.24 30.915 ;
     RECT  2.16 31.185 192.24 31.455 ;
     RECT  2.16 31.725 192.24 31.995 ;
     RECT  2.16 32.265 192.24 32.535 ;
     RECT  2.16 32.805 192.24 33.075 ;
     RECT  2.16 33.345 192.24 33.615 ;
     RECT  2.16 33.885 192.24 34.155 ;
     RECT  2.16 34.425 192.24 34.695 ;
     RECT  2.16 34.965 192.24 35.235 ;
     RECT  2.16 35.505 192.24 35.775 ;
     RECT  2.16 36.045 192.24 36.315 ;
     RECT  2.16 36.585 192.24 36.855 ;
     RECT  2.16 37.125 192.24 37.395 ;
     RECT  2.16 37.665 192.24 37.935 ;
     RECT  2.16 38.205 192.24 38.475 ;
     RECT  2.16 38.745 192.24 39.015 ;
     RECT  2.16 39.285 192.24 39.555 ;
     RECT  2.16 39.825 192.24 40.095 ;
     RECT  2.16 40.365 192.24 40.635 ;
     RECT  2.16 40.905 192.24 41.175 ;
     RECT  2.16 41.445 192.24 41.715 ;
     RECT  2.16 41.985 192.24 42.255 ;
     RECT  2.16 42.525 192.24 42.795 ;
     RECT  2.16 43.065 192.24 43.335 ;
     RECT  2.16 43.605 192.24 43.875 ;
     RECT  2.16 44.145 192.24 44.415 ;
     RECT  2.16 44.685 192.24 44.955 ;
     RECT  2.16 45.225 192.24 45.495 ;
     RECT  2.16 45.765 192.24 46.035 ;
     RECT  2.16 46.305 192.24 46.575 ;
     RECT  2.16 46.845 192.24 47.115 ;
     RECT  2.16 47.385 192.24 47.655 ;
     RECT  2.16 47.925 192.24 48.195 ;
     RECT  2.16 48.465 192.24 48.735 ;
     RECT  2.16 49.005 192.24 49.275 ;
     RECT  2.16 49.545 192.24 49.815 ;
     RECT  2.16 50.085 192.24 50.355 ;
     RECT  2.16 50.625 192.24 50.895 ;
     RECT  2.16 51.165 192.24 51.435 ;
     RECT  2.16 51.705 192.24 51.975 ;
     RECT  2.16 52.245 192.24 52.515 ;
     RECT  2.16 52.785 192.24 53.055 ;
     RECT  2.16 53.325 192.24 53.595 ;
     RECT  2.16 53.865 192.24 54.135 ;
     RECT  2.16 54.405 192.24 54.675 ;
     RECT  2.16 54.945 192.24 55.215 ;
     RECT  2.16 55.485 192.24 55.755 ;
     RECT  2.16 56.025 192.24 56.295 ;
     RECT  2.16 56.565 192.24 56.835 ;
     RECT  2.16 57.105 192.24 57.375 ;
     RECT  2.16 57.645 192.24 57.915 ;
     RECT  2.16 58.185 192.24 58.455 ;
     RECT  2.16 58.725 192.24 58.995 ;
     RECT  2.16 59.265 192.24 59.535 ;
     RECT  2.16 59.805 192.24 60.075 ;
     RECT  2.16 60.345 192.24 60.615 ;
     RECT  2.16 60.885 192.24 61.155 ;
     RECT  2.16 61.425 192.24 61.695 ;
     RECT  2.16 61.965 192.24 62.235 ;
     RECT  2.16 62.505 192.24 62.775 ;
     RECT  2.16 63.045 192.24 63.315 ;
     RECT  2.16 63.585 192.24 63.855 ;
     RECT  2.16 64.125 192.24 64.395 ;
     RECT  2.16 64.665 192.24 64.935 ;
     RECT  2.16 65.205 192.24 65.475 ;
     RECT  2.16 65.745 192.24 66.015 ;
     RECT  2.16 66.285 192.24 66.555 ;
     RECT  2.16 66.825 192.24 67.095 ;
     RECT  2.16 67.365 192.24 67.635 ;
     RECT  2.16 67.905 192.24 68.175 ;
     RECT  2.16 68.445 192.24 68.715 ;
     RECT  2.16 68.985 192.24 69.255 ;
     RECT  2.16 69.525 192.24 69.795 ;
     RECT  2.16 70.065 192.24 70.335 ;
     RECT  2.16 70.605 192.24 70.875 ;
     RECT  2.16 71.145 192.24 71.415 ;
     RECT  2.16 71.685 192.24 71.955 ;
     RECT  2.16 72.225 192.24 72.495 ;
     RECT  2.16 72.765 192.24 73.035 ;
     RECT  2.16 73.305 192.24 73.575 ;
     RECT  2.16 73.845 192.24 74.115 ;
     RECT  2.16 74.385 192.24 74.655 ;
     RECT  2.16 74.925 192.24 75.195 ;
     RECT  2.16 75.465 192.24 75.735 ;
     RECT  2.16 76.005 192.24 76.275 ;
     RECT  2.16 76.545 192.24 76.815 ;
     RECT  2.16 77.085 192.24 77.355 ;
     RECT  2.16 77.625 192.24 77.895 ;
     RECT  2.16 78.165 192.24 78.435 ;
     RECT  2.16 78.705 192.24 78.975 ;
     RECT  2.16 79.245 192.24 79.515 ;
     RECT  2.16 79.785 192.24 80.055 ;
     RECT  2.16 80.325 192.24 80.595 ;
     RECT  2.16 80.865 192.24 81.135 ;
     RECT  2.16 81.405 192.24 81.675 ;
     RECT  2.16 81.945 192.24 82.215 ;
     RECT  2.16 82.485 192.24 82.755 ;
     RECT  2.16 83.025 192.24 83.295 ;
     RECT  2.16 83.565 192.24 83.835 ;
     RECT  2.16 84.105 192.24 84.375 ;
     RECT  2.16 84.645 192.24 84.915 ;
     RECT  2.16 85.185 192.24 85.455 ;
     RECT  2.16 85.725 192.24 85.995 ;
     RECT  2.16 86.265 192.24 86.535 ;
     RECT  2.16 86.805 192.24 87.075 ;
     RECT  2.16 87.345 192.24 87.615 ;
     RECT  2.16 87.885 192.24 88.155 ;
     RECT  2.16 88.425 192.24 88.695 ;
     RECT  2.16 88.965 192.24 89.235 ;
     RECT  2.16 89.505 192.24 89.775 ;
     RECT  2.16 90.045 192.24 90.315 ;
     RECT  2.16 90.585 192.24 90.855 ;
     RECT  2.16 91.125 192.24 91.395 ;
     RECT  2.16 91.665 192.24 91.935 ;
     RECT  2.16 92.205 192.24 92.475 ;
     RECT  2.16 92.745 192.24 93.015 ;
     RECT  2.16 93.285 192.24 93.555 ;
     RECT  2.16 93.825 192.24 94.095 ;
     RECT  2.16 94.365 192.24 94.635 ;
     RECT  2.16 94.905 192.24 95.175 ;
     RECT  2.16 95.445 192.24 95.715 ;
     RECT  2.16 95.985 192.24 96.255 ;
     RECT  2.16 96.525 192.24 96.795 ;
     RECT  2.16 97.065 192.24 97.335 ;
     RECT  2.16 97.605 192.24 97.875 ;
     RECT  2.16 98.145 192.24 98.415 ;
     RECT  2.16 98.685 192.24 98.955 ;
     RECT  2.16 99.225 192.24 99.495 ;
     RECT  2.16 99.765 192.24 100.035 ;
     RECT  2.16 100.305 192.24 100.575 ;
     RECT  2.16 100.845 192.24 101.115 ;
     RECT  2.16 101.385 192.24 101.655 ;
     RECT  2.16 101.925 192.24 102.195 ;
     RECT  2.16 102.465 192.24 102.735 ;
     RECT  2.16 103.005 192.24 103.275 ;
     RECT  2.16 103.545 192.24 103.815 ;
     RECT  2.16 104.085 192.24 104.355 ;
     RECT  2.16 104.625 192.24 104.895 ;
     RECT  2.16 105.165 192.24 105.435 ;
     RECT  2.16 105.705 192.24 105.975 ;
     RECT  2.16 106.245 192.24 106.515 ;
     RECT  2.16 106.785 192.24 107.055 ;
     RECT  2.16 107.325 192.24 107.595 ;
     RECT  2.16 107.865 192.24 108.135 ;
     RECT  2.16 108.405 192.24 108.675 ;
     RECT  2.16 108.945 192.24 109.215 ;
     RECT  2.16 109.485 192.24 109.755 ;
     RECT  2.16 110.025 192.24 110.295 ;
     RECT  2.16 110.565 192.24 110.835 ;
     RECT  2.16 111.105 192.24 111.375 ;
     RECT  2.16 111.645 192.24 111.915 ;
     RECT  2.16 112.185 192.24 112.455 ;
     RECT  2.16 112.725 192.24 112.995 ;
     RECT  2.16 113.265 192.24 113.535 ;
     RECT  2.16 113.805 192.24 114.075 ;
     RECT  2.16 114.345 192.24 114.615 ;
     RECT  2.16 114.885 192.24 115.155 ;
     RECT  2.16 115.425 192.24 115.695 ;
     RECT  2.16 115.965 192.24 116.235 ;
     RECT  2.16 116.505 192.24 116.775 ;
     RECT  2.16 117.045 192.24 117.315 ;
     RECT  2.16 117.585 192.24 117.855 ;
     RECT  2.16 118.125 192.24 118.395 ;
     RECT  2.16 118.665 192.24 118.935 ;
     RECT  2.16 119.205 192.24 119.475 ;
     RECT  2.16 119.745 192.24 120.015 ;
     RECT  2.16 120.285 192.24 120.555 ;
     RECT  2.16 120.825 192.24 121.095 ;
     RECT  2.16 121.365 192.24 121.635 ;
     RECT  2.16 121.905 192.24 122.175 ;
     RECT  2.16 122.445 192.24 122.715 ;
     RECT  2.16 122.985 192.24 123.255 ;
     RECT  2.16 123.525 192.24 123.795 ;
     RECT  2.16 124.065 192.24 124.335 ;
     RECT  2.16 124.605 192.24 124.875 ;
     RECT  2.16 125.145 192.24 125.415 ;
     RECT  2.16 125.685 192.24 125.955 ;
     RECT  2.16 126.225 192.24 126.495 ;
     RECT  2.16 126.765 192.24 127.035 ;
     RECT  2.16 127.305 192.24 127.44 ;
    LAYER RVTP ;
     RECT  2.16 2.295 192.24 2.565 ;
     RECT  2.16 2.835 192.24 3.105 ;
     RECT  2.16 3.375 192.24 3.645 ;
     RECT  2.16 3.915 192.24 4.185 ;
     RECT  2.16 4.455 192.24 4.725 ;
     RECT  2.16 4.995 192.24 5.265 ;
     RECT  2.16 5.535 192.24 5.805 ;
     RECT  2.16 6.075 192.24 6.345 ;
     RECT  2.16 6.615 192.24 6.885 ;
     RECT  2.16 7.155 192.24 7.425 ;
     RECT  2.16 7.695 192.24 7.965 ;
     RECT  2.16 8.235 192.24 8.505 ;
     RECT  2.16 8.775 192.24 9.045 ;
     RECT  2.16 9.315 192.24 9.585 ;
     RECT  2.16 9.855 192.24 10.125 ;
     RECT  2.16 10.395 192.24 10.665 ;
     RECT  2.16 10.935 192.24 11.205 ;
     RECT  2.16 11.475 192.24 11.745 ;
     RECT  2.16 12.015 192.24 12.285 ;
     RECT  2.16 12.555 192.24 12.825 ;
     RECT  2.16 13.095 192.24 13.365 ;
     RECT  2.16 13.635 192.24 13.905 ;
     RECT  2.16 14.175 192.24 14.445 ;
     RECT  2.16 14.715 192.24 14.985 ;
     RECT  2.16 15.255 192.24 15.525 ;
     RECT  2.16 15.795 192.24 16.065 ;
     RECT  2.16 16.335 192.24 16.605 ;
     RECT  2.16 16.875 192.24 17.145 ;
     RECT  2.16 17.415 192.24 17.685 ;
     RECT  2.16 17.955 192.24 18.225 ;
     RECT  2.16 18.495 192.24 18.765 ;
     RECT  2.16 19.035 192.24 19.305 ;
     RECT  2.16 19.575 192.24 19.845 ;
     RECT  2.16 20.115 192.24 20.385 ;
     RECT  2.16 20.655 192.24 20.925 ;
     RECT  2.16 21.195 192.24 21.465 ;
     RECT  2.16 21.735 192.24 22.005 ;
     RECT  2.16 22.275 192.24 22.545 ;
     RECT  2.16 22.815 192.24 23.085 ;
     RECT  2.16 23.355 192.24 23.625 ;
     RECT  2.16 23.895 192.24 24.165 ;
     RECT  2.16 24.435 192.24 24.705 ;
     RECT  2.16 24.975 192.24 25.245 ;
     RECT  2.16 25.515 192.24 25.785 ;
     RECT  2.16 26.055 192.24 26.325 ;
     RECT  2.16 26.595 192.24 26.865 ;
     RECT  2.16 27.135 192.24 27.405 ;
     RECT  2.16 27.675 192.24 27.945 ;
     RECT  2.16 28.215 192.24 28.485 ;
     RECT  2.16 28.755 192.24 29.025 ;
     RECT  2.16 29.295 192.24 29.565 ;
     RECT  2.16 29.835 192.24 30.105 ;
     RECT  2.16 30.375 192.24 30.645 ;
     RECT  2.16 30.915 192.24 31.185 ;
     RECT  2.16 31.455 192.24 31.725 ;
     RECT  2.16 31.995 192.24 32.265 ;
     RECT  2.16 32.535 192.24 32.805 ;
     RECT  2.16 33.075 192.24 33.345 ;
     RECT  2.16 33.615 192.24 33.885 ;
     RECT  2.16 34.155 192.24 34.425 ;
     RECT  2.16 34.695 192.24 34.965 ;
     RECT  2.16 35.235 192.24 35.505 ;
     RECT  2.16 35.775 192.24 36.045 ;
     RECT  2.16 36.315 192.24 36.585 ;
     RECT  2.16 36.855 192.24 37.125 ;
     RECT  2.16 37.395 192.24 37.665 ;
     RECT  2.16 37.935 192.24 38.205 ;
     RECT  2.16 38.475 192.24 38.745 ;
     RECT  2.16 39.015 192.24 39.285 ;
     RECT  2.16 39.555 192.24 39.825 ;
     RECT  2.16 40.095 192.24 40.365 ;
     RECT  2.16 40.635 192.24 40.905 ;
     RECT  2.16 41.175 192.24 41.445 ;
     RECT  2.16 41.715 192.24 41.985 ;
     RECT  2.16 42.255 192.24 42.525 ;
     RECT  2.16 42.795 192.24 43.065 ;
     RECT  2.16 43.335 192.24 43.605 ;
     RECT  2.16 43.875 192.24 44.145 ;
     RECT  2.16 44.415 192.24 44.685 ;
     RECT  2.16 44.955 192.24 45.225 ;
     RECT  2.16 45.495 192.24 45.765 ;
     RECT  2.16 46.035 192.24 46.305 ;
     RECT  2.16 46.575 192.24 46.845 ;
     RECT  2.16 47.115 192.24 47.385 ;
     RECT  2.16 47.655 192.24 47.925 ;
     RECT  2.16 48.195 192.24 48.465 ;
     RECT  2.16 48.735 192.24 49.005 ;
     RECT  2.16 49.275 192.24 49.545 ;
     RECT  2.16 49.815 192.24 50.085 ;
     RECT  2.16 50.355 192.24 50.625 ;
     RECT  2.16 50.895 192.24 51.165 ;
     RECT  2.16 51.435 192.24 51.705 ;
     RECT  2.16 51.975 192.24 52.245 ;
     RECT  2.16 52.515 192.24 52.785 ;
     RECT  2.16 53.055 192.24 53.325 ;
     RECT  2.16 53.595 192.24 53.865 ;
     RECT  2.16 54.135 192.24 54.405 ;
     RECT  2.16 54.675 192.24 54.945 ;
     RECT  2.16 55.215 192.24 55.485 ;
     RECT  2.16 55.755 192.24 56.025 ;
     RECT  2.16 56.295 192.24 56.565 ;
     RECT  2.16 56.835 192.24 57.105 ;
     RECT  2.16 57.375 192.24 57.645 ;
     RECT  2.16 57.915 192.24 58.185 ;
     RECT  2.16 58.455 192.24 58.725 ;
     RECT  2.16 58.995 192.24 59.265 ;
     RECT  2.16 59.535 192.24 59.805 ;
     RECT  2.16 60.075 192.24 60.345 ;
     RECT  2.16 60.615 192.24 60.885 ;
     RECT  2.16 61.155 192.24 61.425 ;
     RECT  2.16 61.695 192.24 61.965 ;
     RECT  2.16 62.235 192.24 62.505 ;
     RECT  2.16 62.775 192.24 63.045 ;
     RECT  2.16 63.315 192.24 63.585 ;
     RECT  2.16 63.855 192.24 64.125 ;
     RECT  2.16 64.395 192.24 64.665 ;
     RECT  2.16 64.935 192.24 65.205 ;
     RECT  2.16 65.475 192.24 65.745 ;
     RECT  2.16 66.015 192.24 66.285 ;
     RECT  2.16 66.555 192.24 66.825 ;
     RECT  2.16 67.095 192.24 67.365 ;
     RECT  2.16 67.635 192.24 67.905 ;
     RECT  2.16 68.175 192.24 68.445 ;
     RECT  2.16 68.715 192.24 68.985 ;
     RECT  2.16 69.255 192.24 69.525 ;
     RECT  2.16 69.795 192.24 70.065 ;
     RECT  2.16 70.335 192.24 70.605 ;
     RECT  2.16 70.875 192.24 71.145 ;
     RECT  2.16 71.415 192.24 71.685 ;
     RECT  2.16 71.955 192.24 72.225 ;
     RECT  2.16 72.495 192.24 72.765 ;
     RECT  2.16 73.035 192.24 73.305 ;
     RECT  2.16 73.575 192.24 73.845 ;
     RECT  2.16 74.115 192.24 74.385 ;
     RECT  2.16 74.655 192.24 74.925 ;
     RECT  2.16 75.195 192.24 75.465 ;
     RECT  2.16 75.735 192.24 76.005 ;
     RECT  2.16 76.275 192.24 76.545 ;
     RECT  2.16 76.815 192.24 77.085 ;
     RECT  2.16 77.355 192.24 77.625 ;
     RECT  2.16 77.895 192.24 78.165 ;
     RECT  2.16 78.435 192.24 78.705 ;
     RECT  2.16 78.975 192.24 79.245 ;
     RECT  2.16 79.515 192.24 79.785 ;
     RECT  2.16 80.055 192.24 80.325 ;
     RECT  2.16 80.595 192.24 80.865 ;
     RECT  2.16 81.135 192.24 81.405 ;
     RECT  2.16 81.675 192.24 81.945 ;
     RECT  2.16 82.215 192.24 82.485 ;
     RECT  2.16 82.755 192.24 83.025 ;
     RECT  2.16 83.295 192.24 83.565 ;
     RECT  2.16 83.835 192.24 84.105 ;
     RECT  2.16 84.375 192.24 84.645 ;
     RECT  2.16 84.915 192.24 85.185 ;
     RECT  2.16 85.455 192.24 85.725 ;
     RECT  2.16 85.995 192.24 86.265 ;
     RECT  2.16 86.535 192.24 86.805 ;
     RECT  2.16 87.075 192.24 87.345 ;
     RECT  2.16 87.615 192.24 87.885 ;
     RECT  2.16 88.155 192.24 88.425 ;
     RECT  2.16 88.695 192.24 88.965 ;
     RECT  2.16 89.235 192.24 89.505 ;
     RECT  2.16 89.775 192.24 90.045 ;
     RECT  2.16 90.315 192.24 90.585 ;
     RECT  2.16 90.855 192.24 91.125 ;
     RECT  2.16 91.395 192.24 91.665 ;
     RECT  2.16 91.935 192.24 92.205 ;
     RECT  2.16 92.475 192.24 92.745 ;
     RECT  2.16 93.015 192.24 93.285 ;
     RECT  2.16 93.555 192.24 93.825 ;
     RECT  2.16 94.095 192.24 94.365 ;
     RECT  2.16 94.635 192.24 94.905 ;
     RECT  2.16 95.175 192.24 95.445 ;
     RECT  2.16 95.715 192.24 95.985 ;
     RECT  2.16 96.255 192.24 96.525 ;
     RECT  2.16 96.795 192.24 97.065 ;
     RECT  2.16 97.335 192.24 97.605 ;
     RECT  2.16 97.875 192.24 98.145 ;
     RECT  2.16 98.415 192.24 98.685 ;
     RECT  2.16 98.955 192.24 99.225 ;
     RECT  2.16 99.495 192.24 99.765 ;
     RECT  2.16 100.035 192.24 100.305 ;
     RECT  2.16 100.575 192.24 100.845 ;
     RECT  2.16 101.115 192.24 101.385 ;
     RECT  2.16 101.655 192.24 101.925 ;
     RECT  2.16 102.195 192.24 102.465 ;
     RECT  2.16 102.735 192.24 103.005 ;
     RECT  2.16 103.275 192.24 103.545 ;
     RECT  2.16 103.815 192.24 104.085 ;
     RECT  2.16 104.355 192.24 104.625 ;
     RECT  2.16 104.895 192.24 105.165 ;
     RECT  2.16 105.435 192.24 105.705 ;
     RECT  2.16 105.975 192.24 106.245 ;
     RECT  2.16 106.515 192.24 106.785 ;
     RECT  2.16 107.055 192.24 107.325 ;
     RECT  2.16 107.595 192.24 107.865 ;
     RECT  2.16 108.135 192.24 108.405 ;
     RECT  2.16 108.675 192.24 108.945 ;
     RECT  2.16 109.215 192.24 109.485 ;
     RECT  2.16 109.755 192.24 110.025 ;
     RECT  2.16 110.295 192.24 110.565 ;
     RECT  2.16 110.835 192.24 111.105 ;
     RECT  2.16 111.375 192.24 111.645 ;
     RECT  2.16 111.915 192.24 112.185 ;
     RECT  2.16 112.455 192.24 112.725 ;
     RECT  2.16 112.995 192.24 113.265 ;
     RECT  2.16 113.535 192.24 113.805 ;
     RECT  2.16 114.075 192.24 114.345 ;
     RECT  2.16 114.615 192.24 114.885 ;
     RECT  2.16 115.155 192.24 115.425 ;
     RECT  2.16 115.695 192.24 115.965 ;
     RECT  2.16 116.235 192.24 116.505 ;
     RECT  2.16 116.775 192.24 117.045 ;
     RECT  2.16 117.315 192.24 117.585 ;
     RECT  2.16 117.855 192.24 118.125 ;
     RECT  2.16 118.395 192.24 118.665 ;
     RECT  2.16 118.935 192.24 119.205 ;
     RECT  2.16 119.475 192.24 119.745 ;
     RECT  2.16 120.015 192.24 120.285 ;
     RECT  2.16 120.555 192.24 120.825 ;
     RECT  2.16 121.095 192.24 121.365 ;
     RECT  2.16 121.635 192.24 121.905 ;
     RECT  2.16 122.175 192.24 122.445 ;
     RECT  2.16 122.715 192.24 122.985 ;
     RECT  2.16 123.255 192.24 123.525 ;
     RECT  2.16 123.795 192.24 124.065 ;
     RECT  2.16 124.335 192.24 124.605 ;
     RECT  2.16 124.875 192.24 125.145 ;
     RECT  2.16 125.415 192.24 125.685 ;
     RECT  2.16 125.955 192.24 126.225 ;
     RECT  2.16 126.495 192.24 126.765 ;
     RECT  2.16 127.035 192.24 127.305 ;
    LAYER M1 ;
     RECT  2.16 2.151 192.24 127.449 ;
    LAYER M2 ;
     RECT  0.031 58.734 0.131 58.752 ;
     RECT  0.175 55.026 0.211 55.044 ;
     RECT  0.103 55.836 0.211 56.394 ;
     RECT  0.211 55.026 0.463 56.394 ;
     RECT  0.031 57.456 0.463 57.474 ;
     RECT  0.463 55.026 0.535 57.474 ;
     RECT  0.103 62.514 1.723 62.532 ;
     RECT  1.723 62.514 1.759 63.072 ;
     RECT  0.535 55.026 2.16 57.906 ;
     RECT  1.759 62.244 2.16 63.072 ;
     RECT  2.16 2.151 192.24 127.449 ;
     RECT  192.24 61.866 193.955 63.504 ;
     RECT  193.955 62.244 194.027 63.504 ;
     RECT  194.027 62.244 194.063 62.262 ;
     RECT  194.027 63.396 194.215 63.504 ;
     RECT  194.215 63.396 194.315 63.882 ;
    LAYER M3 ;
     RECT  2.415 2.143 2.505 2.413 ;
     RECT  7.815 2.143 7.905 2.413 ;
     RECT  13.215 2.143 13.305 2.413 ;
     RECT  18.615 2.143 18.705 2.413 ;
     RECT  24.015 2.143 24.105 2.413 ;
     RECT  29.415 2.143 29.505 2.413 ;
     RECT  34.815 2.143 34.905 2.413 ;
     RECT  40.215 2.143 40.305 2.413 ;
     RECT  45.615 2.143 45.705 2.413 ;
     RECT  51.015 2.143 51.105 2.413 ;
     RECT  56.415 2.143 56.505 2.413 ;
     RECT  61.815 2.143 61.905 2.413 ;
     RECT  67.215 2.143 67.305 2.413 ;
     RECT  72.615 2.143 72.705 2.413 ;
     RECT  78.015 2.143 78.105 2.413 ;
     RECT  83.415 2.143 83.505 2.413 ;
     RECT  88.815 2.143 88.905 2.413 ;
     RECT  94.215 2.143 94.305 2.413 ;
     RECT  99.615 2.143 99.705 2.413 ;
     RECT  105.015 2.143 105.105 2.413 ;
     RECT  110.415 2.143 110.505 2.413 ;
     RECT  115.815 2.143 115.905 2.413 ;
     RECT  121.215 2.143 121.305 2.413 ;
     RECT  126.615 2.143 126.705 2.413 ;
     RECT  132.015 2.143 132.105 2.413 ;
     RECT  137.415 2.143 137.505 2.413 ;
     RECT  142.815 2.143 142.905 2.413 ;
     RECT  148.215 2.143 148.305 2.413 ;
     RECT  153.615 2.143 153.705 2.413 ;
     RECT  159.015 2.143 159.105 2.413 ;
     RECT  164.415 2.143 164.505 2.413 ;
     RECT  169.815 2.143 169.905 2.413 ;
     RECT  175.215 2.143 175.305 2.413 ;
     RECT  180.615 2.143 180.705 2.413 ;
     RECT  186.015 2.143 186.105 2.413 ;
     RECT  191.415 2.143 191.505 2.413 ;
     RECT  2.415 2.413 2.697 54.913 ;
     RECT  2.415 54.913 2.826 54.985 ;
     RECT  2.415 54.985 2.898 55.021 ;
     RECT  2.415 55.021 2.97 55.255 ;
     RECT  0.18 55.021 0.198 55.489 ;
     RECT  2.304 55.255 3.222 55.525 ;
     RECT  2.196 55.525 3.222 55.651 ;
     RECT  2.196 55.651 3.438 55.795 ;
     RECT  0.18 55.489 0.27 55.831 ;
     RECT  6.048 55.819 6.426 55.831 ;
     RECT  2.196 55.795 4.05 55.921 ;
     RECT  18.615 2.413 18.897 55.921 ;
     RECT  6.048 55.831 6.534 55.957 ;
     RECT  19.8 55.921 19.89 55.957 ;
     RECT  6.048 55.957 6.822 55.993 ;
     RECT  11.412 55.957 11.43 55.993 ;
     RECT  18.54 55.921 18.897 55.993 ;
     RECT  19.728 55.957 19.89 55.993 ;
     RECT  0.108 55.831 0.27 56.029 ;
     RECT  18.396 55.993 18.897 56.029 ;
     RECT  19.728 55.993 19.926 56.029 ;
     RECT  7.815 2.413 8.097 56.065 ;
     RECT  11.268 55.993 11.43 56.065 ;
     RECT  13.215 2.413 13.497 56.065 ;
     RECT  21.096 55.921 21.114 56.065 ;
     RECT  5.148 55.651 5.166 56.101 ;
     RECT  6.048 55.993 7.002 56.101 ;
     RECT  10.296 56.065 10.314 56.101 ;
     RECT  21.096 56.065 21.33 56.101 ;
     RECT  5.148 56.101 7.002 56.191 ;
     RECT  10.296 56.101 10.494 56.203 ;
     RECT  11.268 56.065 11.466 56.203 ;
     RECT  21.096 56.101 21.474 56.219 ;
     RECT  0.108 56.029 0.558 56.227 ;
     RECT  5.112 56.191 7.002 56.227 ;
     RECT  7.815 56.065 8.154 56.227 ;
     RECT  13.215 56.065 13.806 56.227 ;
     RECT  19.728 56.029 19.998 56.227 ;
     RECT  9.216 56.101 9.234 56.255 ;
     RECT  2.196 55.921 4.086 56.263 ;
     RECT  5.112 56.227 8.154 56.263 ;
     RECT  13.215 56.227 13.878 56.263 ;
     RECT  14.832 56.065 15.318 56.263 ;
     RECT  18.396 56.029 18.918 56.263 ;
     RECT  10.296 56.203 11.466 56.299 ;
     RECT  13.215 56.263 15.318 56.299 ;
     RECT  10.296 56.299 11.538 56.335 ;
     RECT  18.324 56.263 18.918 56.335 ;
     RECT  22.644 55.687 22.662 56.335 ;
     RECT  18.072 56.335 18.918 56.347 ;
     RECT  19.728 56.227 20.034 56.347 ;
     RECT  2.196 56.263 8.478 56.461 ;
     RECT  13.215 56.299 15.39 56.461 ;
     RECT  12.492 56.461 15.39 56.497 ;
     RECT  22.644 56.335 23.022 56.497 ;
     RECT  9.792 56.335 11.538 56.533 ;
     RECT  12.312 56.497 15.39 56.533 ;
     RECT  22.428 56.497 23.022 56.533 ;
     RECT  9.792 56.533 15.39 56.539 ;
     RECT  17.028 56.497 17.226 56.569 ;
     RECT  9.792 56.539 15.75 56.605 ;
     RECT  16.956 56.569 17.226 56.641 ;
     RECT  18.072 56.347 20.178 56.641 ;
     RECT  22.32 56.533 23.022 56.641 ;
     RECT  9.792 56.605 16.038 56.731 ;
     RECT  16.956 56.641 20.178 56.731 ;
     RECT  2.196 56.461 8.982 56.813 ;
     RECT  22.32 56.641 23.274 56.911 ;
     RECT  24.015 2.413 24.297 56.911 ;
     RECT  2.232 56.813 8.982 57.001 ;
     RECT  9.792 56.731 20.178 57.001 ;
     RECT  21.096 56.219 21.438 57.001 ;
     RECT  22.32 56.911 24.297 57.001 ;
     RECT  2.232 57.001 20.178 57.181 ;
     RECT  21.096 57.001 24.297 57.403 ;
     RECT  0.108 56.227 1.17 57.451 ;
     RECT  2.232 57.181 20.25 57.569 ;
     RECT  17.244 57.569 20.25 57.577 ;
     RECT  21.096 57.403 24.75 57.577 ;
     RECT  26.46 57.067 26.478 57.577 ;
     RECT  17.244 57.577 24.75 57.685 ;
     RECT  26.244 57.577 26.478 57.685 ;
     RECT  17.244 57.685 25.002 57.875 ;
     RECT  26.208 57.685 26.478 57.875 ;
     RECT  26.208 57.875 26.298 57.991 ;
     RECT  17.28 57.875 25.002 58.117 ;
     RECT  0.036 57.451 1.17 58.157 ;
     RECT  17.28 58.117 25.146 58.261 ;
     RECT  26.172 57.991 26.298 58.261 ;
     RECT  29.415 2.413 29.697 58.261 ;
     RECT  2.232 57.569 16.506 58.379 ;
     RECT  2.268 58.379 16.506 58.423 ;
     RECT  17.28 58.261 25.362 58.423 ;
     RECT  26.1 58.261 26.298 58.423 ;
     RECT  27.216 57.991 27.234 58.621 ;
     RECT  2.268 58.423 16.542 58.649 ;
     RECT  2.304 58.649 16.542 58.729 ;
     RECT  17.28 58.423 26.298 58.729 ;
     RECT  27.108 58.621 27.234 58.729 ;
     RECT  0.036 58.157 0.162 58.757 ;
     RECT  2.304 58.729 27.234 58.765 ;
     RECT  29.415 58.261 30.366 58.801 ;
     RECT  2.304 58.765 27.846 58.927 ;
     RECT  28.728 58.801 30.366 58.927 ;
     RECT  2.304 58.927 30.366 59.233 ;
     RECT  1.26 59.371 1.278 59.467 ;
     RECT  2.304 59.233 30.69 59.531 ;
     RECT  1.152 59.467 1.278 59.597 ;
     RECT  0.108 58.757 0.162 59.981 ;
     RECT  2.304 59.531 16.398 60.139 ;
     RECT  0.144 59.981 0.162 60.235 ;
     RECT  17.136 59.531 30.69 60.269 ;
     RECT  1.728 60.139 16.398 60.313 ;
     RECT  17.136 60.269 19.314 60.313 ;
     RECT  0.144 60.235 0.342 60.427 ;
     RECT  0.144 60.427 0.45 60.605 ;
     RECT  0.144 60.605 0.378 60.653 ;
     RECT  32.616 60.421 32.634 60.809 ;
     RECT  20.088 60.269 30.69 60.961 ;
     RECT  31.68 60.859 31.698 60.961 ;
     RECT  20.088 60.961 31.698 60.989 ;
     RECT  1.728 60.313 19.314 61.003 ;
     RECT  20.088 60.989 31.374 61.003 ;
     RECT  34.815 2.413 35.097 61.087 ;
     RECT  35.964 60.691 35.982 61.087 ;
     RECT  34.815 61.087 35.982 61.123 ;
     RECT  0.18 60.653 0.342 61.133 ;
     RECT  37.26 61.051 37.278 61.195 ;
     RECT  37.26 61.195 37.494 61.231 ;
     RECT  1.728 61.003 31.374 61.339 ;
     RECT  34.815 61.123 36.162 61.429 ;
     RECT  38.772 61.123 38.79 61.457 ;
     RECT  34.815 61.429 36.27 61.465 ;
     RECT  37.224 61.231 37.494 61.465 ;
     RECT  105.015 2.413 105.297 61.465 ;
     RECT  33.948 61.435 33.966 61.501 ;
     RECT  34.815 61.465 37.494 61.501 ;
     RECT  1.152 61.339 31.374 61.517 ;
     RECT  33.048 60.961 33.174 61.735 ;
     RECT  33.948 61.501 37.494 61.735 ;
     RECT  38.736 61.663 38.754 61.763 ;
     RECT  0.18 61.133 0.234 61.771 ;
     RECT  0.144 61.771 0.234 61.867 ;
     RECT  107.388 61.663 107.406 61.889 ;
     RECT  1.728 61.517 31.374 61.961 ;
     RECT  0.144 61.867 0.342 61.997 ;
     RECT  33.048 61.735 37.494 62.005 ;
     RECT  22.032 61.961 31.374 62.041 ;
     RECT  32.688 62.005 37.494 62.041 ;
     RECT  38.34 61.969 38.358 62.041 ;
     RECT  22.032 62.041 31.554 62.155 ;
     RECT  32.688 62.041 38.358 62.159 ;
     RECT  22.032 62.155 31.878 62.167 ;
     RECT  32.688 62.159 33.102 62.167 ;
     RECT  110.415 2.413 110.697 62.167 ;
     RECT  193.932 61.861 193.95 62.167 ;
     RECT  22.032 62.167 33.102 62.195 ;
     RECT  193.86 62.167 193.95 62.239 ;
     RECT  110.415 62.167 111.186 62.339 ;
     RECT  102.096 61.429 102.114 62.437 ;
     RECT  110.415 62.339 110.697 62.437 ;
     RECT  109.872 62.437 110.697 62.473 ;
     RECT  193.86 62.239 194.058 62.473 ;
     RECT  102.096 62.437 102.618 62.509 ;
     RECT  117.54 62.275 117.558 62.545 ;
     RECT  106.848 62.311 106.866 62.581 ;
     RECT  23.004 62.195 33.102 62.609 ;
     RECT  117.36 62.545 117.558 62.671 ;
     RECT  31.32 62.609 33.102 62.699 ;
     RECT  102.096 62.509 102.69 62.699 ;
     RECT  106.668 62.581 106.866 62.699 ;
     RECT  109.692 62.473 110.697 62.699 ;
     RECT  0.108 62.509 0.126 62.765 ;
     RECT  23.004 62.609 30.546 62.771 ;
     RECT  32.544 62.699 33.102 62.771 ;
     RECT  102.168 62.699 102.258 62.771 ;
     RECT  117.288 62.671 117.63 62.771 ;
     RECT  1.728 61.961 21.15 62.815 ;
     RECT  98.604 62.743 98.622 62.843 ;
     RECT  102.24 62.771 102.258 62.843 ;
     RECT  33.948 62.159 38.358 62.879 ;
     RECT  1.728 62.815 21.258 62.941 ;
     RECT  22.032 62.195 22.158 62.941 ;
     RECT  107.604 62.851 107.622 62.969 ;
     RECT  109.656 62.743 109.674 62.969 ;
     RECT  1.728 62.941 22.158 63.013 ;
     RECT  23.004 62.771 30.366 63.013 ;
     RECT  104.904 61.465 105.297 63.049 ;
     RECT  1.728 63.013 30.366 63.077 ;
     RECT  104.256 63.049 105.297 63.085 ;
     RECT  104.256 63.085 105.714 63.121 ;
     RECT  103.68 63.121 105.714 63.211 ;
     RECT  34.38 62.879 38.358 63.239 ;
     RECT  103.5 63.211 105.714 63.239 ;
     RECT  36.936 63.239 37.638 63.245 ;
     RECT  2.232 63.077 30.366 63.275 ;
     RECT  34.38 63.239 36.126 63.275 ;
     RECT  37.404 63.245 37.638 63.275 ;
     RECT  109.476 63.121 109.494 63.341 ;
     RECT  193.824 62.473 194.058 63.355 ;
     RECT  107.424 63.121 107.442 63.389 ;
     RECT  193.824 63.355 194.238 63.391 ;
     RECT  2.268 63.275 30.366 63.419 ;
     RECT  108.468 63.391 108.486 63.481 ;
     RECT  110.415 62.699 110.697 63.481 ;
     RECT  37.548 63.275 37.638 63.509 ;
     RECT  105.015 63.239 105.714 63.517 ;
     RECT  103.5 63.239 103.518 63.533 ;
     RECT  2.268 63.419 30.222 63.545 ;
     RECT  37.548 63.509 37.566 63.545 ;
     RECT  108.468 63.481 108.558 63.581 ;
     RECT  110.415 63.481 110.754 63.581 ;
     RECT  38.664 63.391 38.79 63.617 ;
     RECT  193.824 63.391 194.31 63.629 ;
     RECT  2.304 63.545 30.222 63.653 ;
     RECT  34.776 63.275 36.126 63.653 ;
     RECT  38.736 63.617 38.79 63.689 ;
     RECT  0.144 63.547 0.162 63.725 ;
     RECT  193.86 63.629 194.31 63.725 ;
     RECT  33.48 63.211 33.498 63.751 ;
     RECT  21.564 63.653 30.222 63.779 ;
     RECT  32.544 62.771 32.706 63.779 ;
     RECT  35.856 63.653 36.126 63.779 ;
     RECT  38.736 63.689 38.754 63.779 ;
     RECT  105.015 63.517 105.75 63.779 ;
     RECT  32.544 63.779 32.562 63.815 ;
     RECT  34.776 63.653 35.097 63.821 ;
     RECT  193.896 63.725 194.31 63.821 ;
     RECT  31.32 62.699 31.482 63.823 ;
     RECT  33.444 63.751 33.642 63.823 ;
     RECT  2.304 63.653 20.718 63.824 ;
     RECT  108.288 63.661 108.306 63.869 ;
     RECT  105.015 63.779 105.57 63.917 ;
     RECT  194.112 63.821 194.31 63.917 ;
     RECT  194.112 63.917 194.13 64.013 ;
     RECT  21.636 63.779 30.222 64.201 ;
     RECT  2.304 63.824 6.426 64.267 ;
     RECT  21.636 64.201 30.33 64.319 ;
     RECT  0.144 64.459 0.162 64.555 ;
     RECT  7.308 63.824 20.718 64.561 ;
     RECT  21.636 64.319 26.478 64.561 ;
     RECT  2.268 64.267 6.426 64.589 ;
     RECT  35.856 63.779 36.018 64.589 ;
     RECT  2.268 64.589 3.006 64.625 ;
     RECT  3.888 64.589 6.426 64.633 ;
     RECT  7.308 64.561 26.478 64.633 ;
     RECT  0.144 64.555 0.234 64.637 ;
     RECT  27.36 64.319 30.33 64.705 ;
     RECT  31.176 63.823 31.482 64.705 ;
     RECT  0.216 64.637 0.234 64.733 ;
     RECT  27.36 64.705 31.482 64.741 ;
     RECT  3.888 64.633 26.478 64.859 ;
     RECT  2.304 64.625 3.006 64.895 ;
     RECT  36.792 64.741 37.458 64.895 ;
     RECT  3.888 64.859 13.77 64.973 ;
     RECT  14.508 64.859 26.478 65.003 ;
     RECT  27.36 64.741 32.166 65.129 ;
     RECT  25.236 65.003 26.478 65.281 ;
     RECT  3.888 64.973 13.497 65.399 ;
     RECT  27.792 65.129 32.166 65.399 ;
     RECT  2.304 64.895 2.898 65.435 ;
     RECT  27.792 65.399 31.338 65.435 ;
     RECT  33.444 63.823 33.678 65.435 ;
     RECT  3.96 65.399 13.497 65.471 ;
     RECT  27.864 65.435 31.338 65.669 ;
     RECT  3.96 65.471 12.258 65.693 ;
     RECT  3.996 65.693 12.258 65.705 ;
     RECT  2.415 65.435 2.862 65.789 ;
     RECT  4.932 65.705 12.258 65.789 ;
     RECT  14.508 65.003 24.297 65.813 ;
     RECT  5.076 65.789 12.258 65.849 ;
     RECT  13.104 65.471 13.497 65.849 ;
     RECT  14.508 65.813 15.606 65.911 ;
     RECT  5.22 65.849 12.258 65.939 ;
     RECT  16.344 65.813 24.297 65.939 ;
     RECT  3.996 65.705 4.014 65.975 ;
     RECT  5.22 65.939 6.57 65.975 ;
     RECT  7.308 65.939 12.258 65.975 ;
     RECT  13.14 65.849 13.497 65.975 ;
     RECT  13.215 65.975 13.497 65.983 ;
     RECT  5.472 65.975 6.57 66.011 ;
     RECT  14.472 65.911 15.606 66.011 ;
     RECT  13.215 65.983 13.626 66.091 ;
     RECT  5.472 66.011 6.498 66.119 ;
     RECT  16.344 65.939 20.034 66.119 ;
     RECT  5.544 66.119 6.498 66.173 ;
     RECT  25.236 65.281 27.054 66.181 ;
     RECT  5.976 66.173 6.498 66.209 ;
     RECT  7.344 65.975 12.258 66.209 ;
     RECT  13.215 66.091 13.806 66.209 ;
     RECT  14.58 66.011 15.606 66.209 ;
     RECT  25.02 66.181 27.126 66.217 ;
     RECT  27.864 65.669 30.33 66.217 ;
     RECT  20.88 65.939 24.297 66.245 ;
     RECT  25.02 66.217 30.33 66.353 ;
     RECT  5.976 66.209 6.462 66.389 ;
     RECT  7.38 66.209 8.802 66.479 ;
     RECT  9.612 66.209 10.566 66.479 ;
     RECT  11.412 66.209 12.258 66.479 ;
     RECT  21.672 66.245 24.297 66.479 ;
     RECT  25.02 66.353 28.242 66.479 ;
     RECT  9.612 66.479 9.882 66.509 ;
     RECT  13.215 66.209 13.662 66.509 ;
     RECT  5.976 66.389 6.39 66.515 ;
     RECT  7.38 66.479 8.73 66.515 ;
     RECT  11.412 66.479 11.646 66.515 ;
     RECT  6.264 66.515 6.39 66.551 ;
     RECT  28.98 66.353 30.33 66.587 ;
     RECT  26.46 66.479 28.242 66.623 ;
     RECT  6.372 66.551 6.39 66.659 ;
     RECT  26.532 66.623 28.242 66.659 ;
     RECT  21.78 66.479 24.297 66.721 ;
     RECT  25.02 66.479 25.506 66.721 ;
     RECT  11.412 66.515 11.43 66.821 ;
     RECT  14.724 66.209 15.606 66.857 ;
     RECT  16.38 66.119 20.034 66.901 ;
     RECT  20.88 66.245 20.898 66.901 ;
     RECT  14.832 66.857 15.606 66.929 ;
     RECT  9.756 66.509 9.882 67.019 ;
     RECT  26.784 66.659 28.242 67.019 ;
     RECT  9.756 67.019 9.774 67.055 ;
     RECT  16.38 66.901 20.898 67.091 ;
     RECT  27.108 67.019 28.242 67.135 ;
     RECT  28.98 66.587 30.258 67.135 ;
     RECT  14.904 66.929 15.606 67.171 ;
     RECT  16.38 67.091 19.926 67.171 ;
     RECT  20.808 67.091 20.898 67.171 ;
     RECT  7.38 66.515 8.097 67.289 ;
     RECT  21.78 66.721 25.506 67.289 ;
     RECT  14.904 67.171 19.926 67.361 ;
     RECT  15.084 67.361 19.926 67.397 ;
     RECT  15.948 67.397 19.926 67.433 ;
     RECT  20.808 67.171 20.934 67.441 ;
     RECT  16.524 67.433 19.818 67.469 ;
     RECT  21.852 67.289 25.506 67.469 ;
     RECT  110.415 63.581 110.697 67.531 ;
     RECT  6.228 67.405 6.246 67.559 ;
     RECT  15.084 67.397 15.21 67.559 ;
     RECT  16.524 67.469 19.674 67.559 ;
     RECT  20.808 67.441 21.006 67.559 ;
     RECT  21.852 67.469 24.894 67.559 ;
     RECT  15.084 67.559 15.102 67.595 ;
     RECT  20.808 67.559 20.934 67.595 ;
     RECT  21.852 67.559 22.626 67.595 ;
     RECT  17.028 67.559 19.674 67.667 ;
     RECT  23.364 67.559 24.57 67.667 ;
     RECT  2.415 65.789 2.697 67.675 ;
     RECT  20.808 67.595 20.826 67.709 ;
     RECT  21.852 67.595 22.158 67.709 ;
     RECT  17.028 67.667 17.73 67.739 ;
     RECT  21.96 67.709 22.158 67.739 ;
     RECT  23.508 67.667 24.57 67.739 ;
     RECT  26.316 67.441 26.334 67.771 ;
     RECT  27.108 67.135 30.258 67.801 ;
     RECT  24.015 67.739 24.57 67.805 ;
     RECT  2.415 67.675 2.79 67.829 ;
     RECT  18.615 67.667 19.674 67.829 ;
     RECT  21.996 67.739 22.158 67.829 ;
     RECT  26.172 67.771 26.334 67.829 ;
     RECT  21.996 67.829 22.014 67.865 ;
     RECT  26.172 67.829 26.19 67.865 ;
     RECT  2.415 67.829 2.697 67.945 ;
     RECT  31.176 65.669 31.338 68.099 ;
     RECT  2.376 67.945 2.697 68.107 ;
     RECT  2.304 68.107 2.697 68.144 ;
     RECT  27.108 67.801 30.33 68.251 ;
     RECT  26.964 68.251 30.33 68.521 ;
     RECT  31.176 68.099 31.266 68.521 ;
     RECT  26.964 68.521 31.266 68.549 ;
     RECT  26.964 68.549 28.602 68.639 ;
     RECT  26.964 68.639 28.278 68.719 ;
     RECT  26.82 68.719 28.278 68.747 ;
     RECT  26.82 68.747 28.242 68.783 ;
     RECT  33.624 65.435 33.678 69.179 ;
     RECT  33.66 69.179 33.678 69.331 ;
     RECT  34.815 63.821 35.097 69.331 ;
     RECT  26.82 68.783 27.45 69.485 ;
     RECT  33.66 69.331 35.097 69.485 ;
     RECT  27.36 69.485 27.45 69.601 ;
     RECT  28.224 68.783 28.242 69.601 ;
     RECT  33.66 69.485 34.074 70.025 ;
     RECT  35.928 69.457 35.946 70.025 ;
     RECT  27.36 69.601 28.242 70.537 ;
     RECT  27.144 70.537 28.242 70.589 ;
     RECT  32.148 65.399 32.166 71.645 ;
     RECT  36.576 70.069 36.594 73.265 ;
     RECT  29.415 68.549 31.266 73.373 ;
     RECT  37.44 64.895 37.458 73.381 ;
     RECT  37.008 73.381 37.458 73.805 ;
     RECT  29.415 73.373 30.33 74.461 ;
     RECT  29.415 74.461 30.402 74.659 ;
     RECT  31.176 73.373 31.266 74.659 ;
     RECT  37.872 73.921 37.89 74.659 ;
     RECT  37.872 74.659 37.962 74.687 ;
     RECT  34.056 70.025 34.074 75.929 ;
     RECT  34.815 69.485 35.097 76.081 ;
     RECT  37.008 73.805 37.026 76.315 ;
     RECT  34.128 76.081 35.694 76.349 ;
     RECT  37.944 74.687 37.962 76.351 ;
     RECT  34.815 76.349 35.694 76.621 ;
     RECT  34.815 76.621 35.802 76.739 ;
     RECT  36.864 76.315 37.026 76.891 ;
     RECT  34.815 76.739 35.55 76.925 ;
     RECT  27.36 70.589 28.242 77.045 ;
     RECT  37.872 76.351 38.106 77.045 ;
     RECT  38.952 77.161 38.97 77.279 ;
     RECT  36.468 76.891 37.026 77.315 ;
     RECT  37.008 77.315 37.026 77.317 ;
     RECT  37.872 77.045 37.89 77.317 ;
     RECT  40.215 2.413 40.497 77.431 ;
     RECT  39.24 77.395 39.258 77.453 ;
     RECT  37.008 77.317 37.89 77.549 ;
     RECT  37.008 77.549 37.026 77.585 ;
     RECT  40.14 77.431 40.497 77.585 ;
     RECT  45.615 2.413 45.897 77.701 ;
     RECT  41.616 77.251 41.634 77.855 ;
     RECT  27.396 77.045 28.242 77.935 ;
     RECT  29.415 74.659 31.266 78.241 ;
     RECT  27.36 77.935 28.242 78.431 ;
     RECT  29.376 78.241 31.266 78.475 ;
     RECT  34.815 76.925 35.097 78.475 ;
     RECT  27.72 78.431 28.242 78.511 ;
     RECT  29.016 78.475 31.266 78.511 ;
     RECT  34.164 78.475 35.097 78.511 ;
     RECT  27.72 78.511 31.266 78.665 ;
     RECT  32.76 71.761 32.778 78.781 ;
     RECT  32.22 78.781 32.778 79.045 ;
     RECT  34.164 78.511 35.154 79.045 ;
     RECT  34.164 79.045 35.442 79.051 ;
     RECT  32.22 79.045 32.886 79.085 ;
     RECT  36.54 79.051 36.558 79.141 ;
     RECT  34.164 79.051 35.586 79.205 ;
     RECT  36.504 79.141 36.558 79.213 ;
     RECT  34.164 79.205 35.097 79.249 ;
     RECT  33.948 79.249 35.097 79.475 ;
     RECT  36.504 79.213 36.666 79.511 ;
     RECT  27.936 78.665 31.266 79.591 ;
     RECT  32.22 79.085 32.526 79.591 ;
     RECT  36.648 79.511 36.666 79.591 ;
     RECT  34.092 79.475 35.097 79.709 ;
     RECT  27.432 79.591 32.526 79.745 ;
     RECT  27.432 79.745 31.266 79.979 ;
     RECT  32.436 79.745 32.526 80.015 ;
     RECT  35.892 79.591 35.91 80.015 ;
     RECT  39.276 79.681 39.294 80.015 ;
     RECT  36.648 79.591 36.81 80.131 ;
     RECT  36.648 80.131 37.026 80.249 ;
     RECT  45.615 77.701 46.098 80.251 ;
     RECT  33.012 80.131 33.03 80.285 ;
     RECT  34.164 79.709 35.097 80.285 ;
     RECT  44.46 80.131 44.478 80.285 ;
     RECT  45.324 80.251 46.098 80.291 ;
     RECT  45.615 80.291 46.098 80.329 ;
     RECT  34.815 80.285 35.097 80.401 ;
     RECT  45.615 80.329 46.35 80.491 ;
     RECT  34.815 80.401 35.154 80.527 ;
     RECT  38.844 80.401 38.97 80.527 ;
     RECT  27.612 79.979 31.266 80.555 ;
     RECT  36.648 80.249 36.666 80.573 ;
     RECT  38.808 80.527 38.97 80.573 ;
     RECT  40.215 77.585 40.497 80.671 ;
     RECT  45.615 80.491 46.386 80.671 ;
     RECT  43.74 80.635 43.758 80.761 ;
     RECT  38.844 80.573 38.97 80.789 ;
     RECT  43.452 80.761 43.758 80.789 ;
     RECT  27.648 80.555 31.266 80.797 ;
     RECT  38.844 80.789 38.862 80.825 ;
     RECT  39.744 80.671 40.497 80.825 ;
     RECT  43.452 80.789 43.47 80.861 ;
     RECT  45.615 80.671 46.422 80.905 ;
     RECT  34.815 80.527 35.262 81.019 ;
     RECT  45.615 80.905 46.458 81.059 ;
     RECT  40.176 80.825 40.497 81.095 ;
     RECT  34.815 81.019 35.478 81.211 ;
     RECT  40.215 81.095 40.497 81.211 ;
     RECT  41.832 81.175 41.85 81.211 ;
     RECT  36.612 81.211 36.63 81.301 ;
     RECT  40.215 81.211 40.806 81.329 ;
     RECT  41.832 81.211 41.994 81.329 ;
     RECT  34.815 81.211 35.622 81.445 ;
     RECT  36.612 81.301 36.666 81.481 ;
     RECT  41.832 81.329 41.85 81.485 ;
     RECT  36.504 81.481 36.666 81.599 ;
     RECT  27.648 80.797 31.374 81.715 ;
     RECT  36.504 81.599 36.63 82.013 ;
     RECT  27.648 81.715 31.41 82.061 ;
     RECT  28.008 82.061 31.41 82.175 ;
     RECT  28.296 82.175 31.41 82.291 ;
     RECT  32.22 81.913 32.238 82.291 ;
     RECT  28.296 82.291 32.238 82.409 ;
     RECT  28.44 82.409 32.238 82.417 ;
     RECT  33.876 81.481 33.894 82.525 ;
     RECT  37.872 77.549 37.89 82.525 ;
     RECT  28.44 82.417 32.274 82.561 ;
     RECT  33.192 82.525 33.894 82.561 ;
     RECT  34.815 81.445 35.73 82.561 ;
     RECT  48.6 82.075 48.618 82.561 ;
     RECT  48.564 82.561 48.618 82.637 ;
     RECT  45.615 81.059 46.422 82.651 ;
     RECT  28.44 82.561 32.31 82.679 ;
     RECT  28.44 82.679 28.458 82.715 ;
     RECT  36.504 82.013 36.522 82.715 ;
     RECT  48.6 82.637 48.618 82.723 ;
     RECT  48.6 82.723 48.942 82.751 ;
     RECT  38.736 82.561 38.754 82.759 ;
     RECT  48.924 82.751 48.942 82.781 ;
     RECT  29.196 82.679 32.31 82.795 ;
     RECT  40.215 81.329 40.497 82.795 ;
     RECT  37.764 82.525 37.89 82.831 ;
     RECT  38.736 82.759 38.898 82.831 ;
     RECT  40.215 82.795 40.77 82.831 ;
     RECT  38.736 82.831 39.366 82.939 ;
     RECT  40.215 82.831 40.878 82.939 ;
     RECT  29.196 82.795 32.418 82.985 ;
     RECT  38.736 82.939 40.878 82.985 ;
     RECT  29.268 82.985 32.418 83.057 ;
     RECT  33.192 82.561 35.73 83.065 ;
     RECT  39.672 82.985 40.878 83.093 ;
     RECT  29.412 83.057 32.418 83.101 ;
     RECT  33.156 83.065 35.73 83.101 ;
     RECT  40.215 83.093 40.878 83.101 ;
     RECT  38.736 82.985 38.898 83.219 ;
     RECT  29.412 83.101 35.73 83.264 ;
     RECT  42.768 81.211 42.786 83.371 ;
     RECT  37.764 82.831 37.962 83.489 ;
     RECT  38.736 83.219 38.754 83.489 ;
     RECT  40.215 83.101 40.986 83.641 ;
     RECT  42.408 83.371 42.786 83.641 ;
     RECT  40.215 83.641 42.786 83.759 ;
     RECT  40.215 83.759 40.986 83.795 ;
     RECT  41.796 83.759 42.786 83.795 ;
     RECT  29.415 83.264 35.73 83.911 ;
     RECT  42.192 83.795 42.786 84.065 ;
     RECT  29.415 83.911 36.342 84.109 ;
     RECT  43.74 84.139 43.758 84.181 ;
     RECT  47.808 81.751 47.826 84.181 ;
     RECT  43.74 84.181 43.902 84.209 ;
     RECT  29.415 84.109 36.414 84.271 ;
     RECT  45.615 82.651 46.494 84.271 ;
     RECT  51.015 2.413 51.297 84.271 ;
     RECT  37.764 83.489 37.782 84.299 ;
     RECT  43.884 84.209 43.902 84.299 ;
     RECT  45.504 84.271 46.494 84.317 ;
     RECT  29.415 84.271 36.45 84.335 ;
     RECT  42.552 84.065 42.786 84.335 ;
     RECT  47.376 84.181 47.826 84.335 ;
     RECT  30.852 84.335 36.45 84.569 ;
     RECT  30.852 84.569 32.85 84.605 ;
     RECT  51.015 84.271 51.894 84.605 ;
     RECT  53.532 84.571 53.55 84.611 ;
     RECT  33.624 84.569 36.45 84.677 ;
     RECT  33.66 84.677 36.45 84.721 ;
     RECT  45.615 84.317 46.494 84.721 ;
     RECT  33.66 84.721 36.486 84.839 ;
     RECT  42.768 84.335 42.786 84.875 ;
     RECT  54.504 84.721 55.062 84.875 ;
     RECT  34.776 84.839 36.486 84.991 ;
     RECT  34.776 84.991 36.594 85.081 ;
     RECT  47.808 84.335 47.826 85.099 ;
     RECT  54.612 84.875 55.062 85.145 ;
     RECT  31.248 84.605 32.85 85.181 ;
     RECT  34.776 85.081 36.882 85.225 ;
     RECT  34.776 85.225 37.386 85.261 ;
     RECT  45.615 84.721 46.854 85.261 ;
     RECT  47.664 85.099 47.826 85.261 ;
     RECT  34.776 85.261 37.566 85.289 ;
     RECT  56.415 2.413 56.697 85.387 ;
     RECT  34.815 85.289 37.566 85.415 ;
     RECT  45.615 85.261 47.826 85.415 ;
     RECT  48.6 85.261 48.618 85.415 ;
     RECT  55.152 85.261 55.278 85.469 ;
     RECT  46.728 85.415 47.826 85.483 ;
     RECT  46.728 85.483 48.366 85.517 ;
     RECT  53.136 85.579 53.154 85.621 ;
     RECT  32.652 85.181 32.85 85.685 ;
     RECT  50.184 85.351 50.202 85.685 ;
     RECT  32.76 85.685 32.85 85.801 ;
     RECT  33.66 84.839 33.966 85.801 ;
     RECT  53.064 85.621 53.154 85.801 ;
     RECT  56.124 85.387 56.697 85.801 ;
     RECT  34.815 85.415 37.314 85.829 ;
     RECT  32.76 85.801 32.886 85.919 ;
     RECT  33.66 85.801 34.074 85.919 ;
     RECT  35.964 85.829 37.314 85.919 ;
     RECT  46.728 85.517 47.574 85.919 ;
     RECT  52.992 85.801 53.298 85.919 ;
     RECT  55.692 85.801 56.697 85.919 ;
     RECT  32.76 85.919 32.778 85.955 ;
     RECT  52.992 85.919 53.01 85.955 ;
     RECT  54.072 85.801 54.09 85.955 ;
     RECT  38.88 85.531 38.898 86.035 ;
     RECT  48.348 85.517 48.366 86.063 ;
     RECT  33.66 85.919 33.786 86.189 ;
     RECT  34.815 85.829 35.226 86.189 ;
     RECT  33.66 86.189 33.678 86.225 ;
     RECT  38.736 86.035 38.898 86.225 ;
     RECT  35.964 85.919 36.954 86.237 ;
     RECT  49.428 86.071 49.446 86.305 ;
     RECT  36.396 86.237 36.954 86.333 ;
     RECT  38.88 86.225 38.898 86.341 ;
     RECT  34.815 86.189 35.154 86.459 ;
     RECT  36.576 86.333 36.954 86.459 ;
     RECT  36.576 86.459 36.81 86.495 ;
     RECT  49.428 86.305 49.77 86.495 ;
     RECT  56.124 85.919 56.697 86.701 ;
     RECT  49.752 86.495 49.77 86.729 ;
     RECT  59.148 86.611 59.274 86.729 ;
     RECT  36.576 86.495 36.594 86.765 ;
     RECT  57.564 86.611 57.582 86.765 ;
     RECT  49.86 86.845 50.274 86.881 ;
     RECT  51.015 84.605 51.297 86.881 ;
     RECT  49.86 86.881 51.297 86.999 ;
     RECT  49.86 86.999 49.878 87.035 ;
     RECT  44.676 84.181 44.694 87.575 ;
     RECT  49.32 87.787 49.338 87.961 ;
     RECT  48.996 87.961 49.338 88.259 ;
     RECT  48.996 88.259 49.014 88.301 ;
     RECT  51.015 86.999 51.297 88.321 ;
     RECT  46.728 85.919 46.854 88.349 ;
     RECT  50.832 88.321 51.297 88.925 ;
     RECT  50.94 88.925 51.297 89.309 ;
     RECT  52.128 89.311 53.226 89.429 ;
     RECT  52.128 89.429 52.326 89.699 ;
     RECT  52.128 89.699 52.146 89.735 ;
     RECT  53.208 89.429 53.226 89.735 ;
     RECT  46.728 88.349 46.746 89.969 ;
     RECT  53.424 89.851 53.622 89.969 ;
     RECT  45.615 85.415 45.897 89.977 ;
     RECT  48.636 89.941 48.654 89.995 ;
     RECT  45.615 89.977 46.494 90.029 ;
     RECT  53.424 89.969 53.442 90.029 ;
     RECT  47.7 87.691 47.718 90.121 ;
     RECT  48.636 89.995 49.086 90.121 ;
     RECT  58.032 89.941 58.05 90.247 ;
     RECT  47.592 90.121 49.086 90.275 ;
     RECT  58.032 90.247 58.23 90.275 ;
     RECT  58.212 90.275 58.23 90.419 ;
     RECT  47.7 90.275 49.086 90.509 ;
     RECT  47.7 90.509 47.754 90.545 ;
     RECT  48.636 90.509 49.086 90.545 ;
     RECT  47.7 90.545 47.718 90.779 ;
     RECT  50.004 90.661 50.022 90.931 ;
     RECT  51.015 89.309 51.297 90.931 ;
     RECT  61.815 2.413 62.097 90.931 ;
     RECT  61.815 90.931 62.262 91.049 ;
     RECT  63.036 90.931 63.486 91.085 ;
     RECT  50.004 90.931 51.297 91.327 ;
     RECT  59.256 86.729 59.274 91.327 ;
     RECT  50.004 91.327 51.822 91.355 ;
     RECT  63.288 91.085 63.486 91.355 ;
     RECT  51.015 91.355 51.822 91.373 ;
     RECT  59.256 91.327 59.742 91.373 ;
     RECT  61.815 91.049 62.097 91.399 ;
     RECT  59.256 91.373 59.274 91.625 ;
     RECT  61.308 91.399 62.097 91.667 ;
     RECT  52.776 91.471 52.794 91.741 ;
     RECT  52.776 91.741 53.118 91.819 ;
     RECT  52.776 91.819 53.154 92.011 ;
     RECT  52.776 92.011 53.298 92.129 ;
     RECT  52.776 92.129 53.118 92.165 ;
     RECT  54.72 91.831 54.738 92.165 ;
     RECT  61.815 91.667 62.097 92.281 ;
     RECT  50.004 91.355 50.022 92.435 ;
     RECT  61.815 92.281 62.19 92.635 ;
     RECT  56.088 86.701 56.697 92.705 ;
     RECT  63.468 91.355 63.486 92.821 ;
     RECT  61.815 92.635 62.622 92.957 ;
     RECT  65.628 92.923 65.646 92.975 ;
     RECT  63.468 92.821 63.702 93.091 ;
     RECT  67.215 2.413 67.497 93.091 ;
     RECT  65.808 93.091 65.826 93.209 ;
     RECT  63.468 93.091 64.17 93.245 ;
     RECT  61.815 92.957 62.097 93.631 ;
     RECT  56.124 92.705 56.697 93.659 ;
     RECT  61.812 93.631 62.097 93.749 ;
     RECT  61.815 93.749 62.097 93.901 ;
     RECT  61.815 93.901 62.154 94.441 ;
     RECT  63.468 93.245 63.486 94.531 ;
     RECT  61.815 94.441 62.334 94.559 ;
     RECT  61.815 94.559 62.262 94.595 ;
     RECT  66.6 93.091 67.497 94.667 ;
     RECT  63.324 94.531 63.99 94.865 ;
     RECT  63.468 94.865 63.99 94.973 ;
     RECT  63.504 94.973 63.99 94.981 ;
     RECT  63.504 94.981 64.098 95.171 ;
     RECT  64.08 95.171 64.098 95.251 ;
     RECT  64.08 95.251 64.314 95.369 ;
     RECT  64.08 95.369 64.134 95.549 ;
     RECT  66.672 94.667 67.497 96.331 ;
     RECT  66.672 96.331 67.626 96.449 ;
     RECT  72.615 2.413 72.897 96.565 ;
     RECT  70.488 96.565 70.506 96.571 ;
     RECT  72.615 96.565 73.278 96.571 ;
     RECT  72.036 96.571 73.278 96.605 ;
     RECT  72.036 96.605 72.897 96.629 ;
     RECT  70.488 96.571 71.226 96.755 ;
     RECT  74.196 96.601 74.394 96.755 ;
     RECT  61.815 94.595 62.097 98.077 ;
     RECT  56.34 93.659 56.697 98.105 ;
     RECT  61.812 98.077 62.097 98.141 ;
     RECT  66.672 96.449 67.497 98.149 ;
     RECT  65.088 95.521 65.106 98.185 ;
     RECT  66.636 98.149 67.497 98.311 ;
     RECT  60.948 92.011 60.966 98.339 ;
     RECT  65.088 98.185 65.538 98.339 ;
     RECT  68.508 98.077 68.526 98.347 ;
     RECT  74.376 96.755 74.394 98.347 ;
     RECT  68.508 98.347 68.706 98.375 ;
     RECT  74.376 98.347 74.79 98.491 ;
     RECT  68.688 98.375 68.706 98.519 ;
     RECT  72.615 96.629 72.897 98.581 ;
     RECT  74.376 98.491 74.934 98.581 ;
     RECT  64.08 95.549 64.098 98.587 ;
     RECT  74.376 98.581 75.294 98.618 ;
     RECT  72.615 98.581 73.53 98.761 ;
     RECT  74.34 98.618 75.294 98.765 ;
     RECT  31.248 85.181 31.266 98.789 ;
     RECT  71.208 98.581 71.226 98.879 ;
     RECT  65.088 98.339 65.394 98.915 ;
     RECT  69.552 98.581 69.57 98.915 ;
     RECT  72.396 98.761 73.53 98.915 ;
     RECT  74.376 98.765 75.294 98.915 ;
     RECT  76.104 98.491 76.122 98.915 ;
     RECT  72.396 98.915 72.897 98.995 ;
     RECT  64.08 98.587 64.314 99.031 ;
     RECT  64.08 99.031 64.458 99.059 ;
     RECT  64.296 99.059 64.458 99.149 ;
     RECT  76.644 99.031 76.662 99.149 ;
     RECT  66.6 98.311 67.497 99.163 ;
     RECT  64.296 99.149 64.314 99.185 ;
     RECT  78.015 2.413 78.297 99.301 ;
     RECT  66.348 99.163 67.497 99.661 ;
     RECT  68.616 99.121 68.634 99.661 ;
     RECT  66.348 99.661 68.634 99.697 ;
     RECT  66.348 99.697 68.814 99.725 ;
     RECT  66.348 99.725 67.914 99.773 ;
     RECT  75.276 98.915 75.294 99.841 ;
     RECT  68.796 99.725 68.814 99.869 ;
     RECT  74.376 98.915 74.394 99.931 ;
     RECT  77.292 99.301 78.297 99.931 ;
     RECT  66.348 99.773 67.497 99.959 ;
     RECT  77.184 99.931 78.297 99.959 ;
     RECT  77.184 99.959 77.202 99.995 ;
     RECT  75.276 99.841 75.33 100.201 ;
     RECT  73.98 99.931 74.394 100.229 ;
     RECT  74.376 100.229 74.394 100.381 ;
     RECT  75.276 100.201 75.438 100.381 ;
     RECT  74.376 100.381 75.438 100.535 ;
     RECT  75.24 100.535 75.438 100.651 ;
     RECT  66.6 99.959 67.497 100.805 ;
     RECT  75.24 100.651 75.69 100.805 ;
     RECT  75.42 100.805 75.69 101.849 ;
     RECT  75.672 101.849 75.69 102.001 ;
     RECT  75.672 102.001 75.798 102.091 ;
     RECT  65.376 98.915 65.394 102.119 ;
     RECT  75.672 102.091 76.014 102.271 ;
     RECT  75.672 102.271 76.194 102.389 ;
     RECT  75.672 102.389 75.798 102.425 ;
     RECT  65.556 102.271 65.574 102.695 ;
     RECT  74.376 100.535 74.394 102.695 ;
     RECT  67.215 100.805 67.497 102.811 ;
     RECT  75.672 102.425 75.69 102.811 ;
     RECT  66.78 102.811 67.497 103 ;
     RECT  66.6 103 67.497 103.037 ;
     RECT  67.215 103.037 67.497 103.081 ;
     RECT  76.968 102.271 76.986 103.195 ;
     RECT  74.664 103.195 74.682 103.235 ;
     RECT  76.428 103.195 76.986 103.577 ;
     RECT  76.968 103.577 76.986 104.287 ;
     RECT  78.015 99.959 78.297 104.287 ;
     RECT  76.968 104.287 78.297 104.315 ;
     RECT  75.42 102.811 75.69 104.863 ;
     RECT  77.616 104.315 78.297 104.971 ;
     RECT  75.42 104.863 76.122 105.331 ;
     RECT  67.215 103.081 67.59 105.395 ;
     RECT  77.616 104.971 78.354 106.169 ;
     RECT  78.015 106.169 78.354 106.825 ;
     RECT  78.015 106.825 78.498 106.861 ;
     RECT  78.015 106.861 78.678 106.979 ;
     RECT  89.928 106.861 90.09 106.979 ;
     RECT  79.452 106.861 79.47 107.015 ;
     RECT  82.296 106.987 82.314 107.159 ;
     RECT  78.015 106.979 78.498 107.165 ;
     RECT  75.06 105.331 76.122 107.249 ;
     RECT  90.072 106.979 90.09 107.285 ;
     RECT  82.26 107.401 82.278 107.519 ;
     RECT  90.828 107.401 90.846 107.519 ;
     RECT  83.415 2.413 83.697 107.671 ;
     RECT  82.224 107.635 82.242 107.741 ;
     RECT  91.08 107.635 91.098 107.741 ;
     RECT  69.84 100.849 69.858 108.329 ;
     RECT  75.42 107.249 76.122 108.329 ;
     RECT  83.196 107.671 83.697 108.409 ;
     RECT  85.572 108.445 85.59 108.481 ;
     RECT  82.656 108.409 83.697 108.599 ;
     RECT  85.392 108.481 85.734 108.599 ;
     RECT  81.144 108.301 81.162 108.635 ;
     RECT  85.392 108.599 85.41 108.635 ;
     RECT  86.508 108.481 86.526 108.635 ;
     RECT  72.288 98.995 72.897 108.751 ;
     RECT  78.015 107.165 78.354 108.751 ;
     RECT  83.34 108.599 83.697 108.751 ;
     RECT  84.6 108.679 84.618 108.751 ;
     RECT  76.068 108.329 76.122 108.779 ;
     RECT  72.288 108.751 73.062 108.869 ;
     RECT  74.124 108.751 74.142 108.905 ;
     RECT  86.688 108.751 87.318 108.905 ;
     RECT  74.376 109.021 74.394 109.175 ;
     RECT  78.015 108.751 78.678 109.175 ;
     RECT  87.3 108.905 87.318 109.243 ;
     RECT  76.068 108.779 76.086 109.291 ;
     RECT  87.3 109.243 87.498 109.291 ;
     RECT  88.815 2.413 89.097 109.291 ;
     RECT  83.34 108.751 83.754 109.381 ;
     RECT  84.492 108.751 84.654 109.381 ;
     RECT  88.416 109.291 89.097 109.381 ;
     RECT  90.108 109.243 90.126 109.381 ;
     RECT  81.684 109.339 81.702 109.409 ;
     RECT  87.3 109.291 87.642 109.409 ;
     RECT  87.3 109.409 87.57 109.445 ;
     RECT  88.416 109.381 90.126 109.445 ;
     RECT  88.815 109.445 90.126 109.481 ;
     RECT  83.34 109.381 84.654 109.561 ;
     RECT  75.636 109.291 76.086 109.679 ;
     RECT  78.015 109.175 78.57 109.679 ;
     RECT  75.636 109.679 75.654 109.715 ;
     RECT  78.015 109.679 78.39 109.715 ;
     RECT  82.728 109.561 84.654 109.723 ;
     RECT  79.308 109.561 79.362 109.831 ;
     RECT  81.792 109.561 81.99 109.831 ;
     RECT  82.728 109.723 84.726 109.831 ;
     RECT  86.04 109.561 86.058 109.831 ;
     RECT  91.116 109.561 91.134 109.831 ;
     RECT  92.052 107.671 92.07 109.831 ;
     RECT  81.792 109.831 84.726 109.853 ;
     RECT  79.308 109.831 79.938 109.949 ;
     RECT  81.792 109.853 84.654 109.949 ;
     RECT  81.792 109.949 83.697 109.985 ;
     RECT  84.564 109.949 84.654 109.985 ;
     RECT  86.04 109.831 86.67 109.985 ;
     RECT  81.792 109.985 82.638 110.021 ;
     RECT  86.04 109.985 86.274 110.101 ;
     RECT  90.108 109.481 90.126 110.101 ;
     RECT  91.116 109.831 92.07 110.101 ;
     RECT  85.752 110.101 86.274 110.219 ;
     RECT  90.108 110.101 90.27 110.219 ;
     RECT  79.308 109.949 79.758 110.255 ;
     RECT  85.752 110.219 86.058 110.255 ;
     RECT  87.552 109.445 87.57 110.255 ;
     RECT  90.108 110.219 90.126 110.255 ;
     RECT  81.792 110.021 81.99 110.371 ;
     RECT  88.815 109.481 89.097 110.371 ;
     RECT  91.116 110.101 92.142 110.371 ;
     RECT  81.684 110.371 81.99 110.399 ;
     RECT  79.56 110.255 79.758 110.489 ;
     RECT  80.856 110.335 80.874 110.489 ;
     RECT  81.684 110.399 81.702 110.525 ;
     RECT  84.636 109.985 84.654 110.525 ;
     RECT  91.044 110.371 92.142 110.525 ;
     RECT  79.56 110.489 79.578 110.531 ;
     RECT  85.752 110.255 85.77 110.641 ;
     RECT  91.296 110.525 92.142 110.641 ;
     RECT  91.296 110.641 92.682 110.795 ;
     RECT  83.415 109.985 83.697 111.403 ;
     RECT  85.464 110.641 85.77 111.541 ;
     RECT  94.215 2.413 94.497 111.541 ;
     RECT  93.672 111.541 94.497 111.547 ;
     RECT  83.415 111.403 83.79 111.581 ;
     RECT  88.815 110.371 89.55 111.605 ;
     RECT  92.052 110.795 92.682 111.605 ;
     RECT  93.672 111.547 94.626 111.677 ;
     RECT  98.604 111.547 98.622 111.677 ;
     RECT  85.464 111.541 85.914 111.787 ;
     RECT  85.464 111.787 85.986 111.839 ;
     RECT  93.672 111.677 94.497 111.839 ;
     RECT  85.464 111.839 85.914 112.019 ;
     RECT  86.904 111.991 86.922 112.145 ;
     RECT  87.192 112.261 87.75 112.415 ;
     RECT  87.732 112.415 87.75 112.621 ;
     RECT  92.124 111.605 92.682 112.621 ;
     RECT  85.644 112.019 85.914 112.649 ;
     RECT  85.644 112.649 85.662 112.685 ;
     RECT  87.732 112.621 87.822 112.729 ;
     RECT  90.396 111.541 90.414 112.729 ;
     RECT  87.732 112.729 87.93 112.801 ;
     RECT  88.815 111.605 89.097 112.801 ;
     RECT  90.396 112.729 90.666 112.801 ;
     RECT  91.8 112.621 92.682 112.801 ;
     RECT  90.396 112.801 90.738 112.829 ;
     RECT  90.648 112.829 90.738 112.877 ;
     RECT  87.732 112.801 87.966 112.919 ;
     RECT  87.732 112.919 87.93 112.955 ;
     RECT  88.74 112.801 89.097 112.991 ;
     RECT  90.648 112.877 90.666 113.063 ;
     RECT  94.215 111.839 94.497 113.071 ;
     RECT  99.615 2.413 99.897 113.071 ;
     RECT  91.656 112.801 92.682 113.225 ;
     RECT  92.124 113.225 92.682 113.341 ;
     RECT  94.215 113.071 94.806 113.341 ;
     RECT  92.124 113.341 92.754 113.459 ;
     RECT  94.215 113.341 95.526 113.503 ;
     RECT  94.215 113.503 95.562 113.659 ;
     RECT  92.124 113.459 92.682 113.729 ;
     RECT  94.215 113.659 96.03 113.981 ;
     RECT  96.948 113.881 96.966 114.539 ;
     RECT  98.604 114.523 98.622 114.575 ;
     RECT  92.196 113.729 92.682 114.583 ;
     RECT  99.615 113.071 100.314 114.691 ;
     RECT  99.612 114.691 100.314 114.961 ;
     RECT  92.052 114.583 92.682 115.079 ;
     RECT  99.576 114.961 100.314 115.079 ;
     RECT  92.124 115.079 92.682 115.925 ;
     RECT  94.215 113.981 95.562 115.925 ;
     RECT  96.912 115.591 96.93 116.041 ;
     RECT  96.912 116.041 97.722 116.159 ;
     RECT  101.7 116.041 101.718 116.159 ;
     RECT  96.912 116.159 97.578 116.195 ;
     RECT  103.104 116.155 103.122 116.195 ;
     RECT  103.284 116.311 103.302 116.429 ;
     RECT  102.528 116.239 102.546 116.465 ;
     RECT  104.148 116.311 104.166 116.581 ;
     RECT  105.015 63.917 105.297 116.581 ;
     RECT  94.215 115.925 94.914 116.699 ;
     RECT  104.148 116.581 105.297 116.735 ;
     RECT  92.664 115.925 92.682 117.005 ;
     RECT  98.64 116.671 98.658 117.121 ;
     RECT  98.64 117.121 98.802 117.275 ;
     RECT  99.615 115.079 100.314 117.391 ;
     RECT  97.56 116.195 97.578 118.049 ;
     RECT  97.92 118.201 97.938 118.561 ;
     RECT  98.784 117.275 98.802 118.561 ;
     RECT  97.92 118.561 98.802 118.741 ;
     RECT  99.615 117.391 100.782 118.741 ;
     RECT  97.92 118.741 100.782 118.859 ;
     RECT  97.92 118.859 97.938 118.895 ;
     RECT  98.784 118.859 100.782 118.895 ;
     RECT  106.308 115.051 106.326 119.975 ;
     RECT  99.615 118.895 100.782 120.451 ;
     RECT  99.615 120.451 101.358 120.631 ;
     RECT  99.615 120.631 101.394 120.701 ;
     RECT  99.615 120.701 101.358 120.749 ;
     RECT  104.292 116.735 105.297 120.785 ;
     RECT  99.615 120.749 100.782 121.055 ;
     RECT  104.796 120.785 105.297 121.171 ;
     RECT  104.796 121.171 105.462 122.521 ;
     RECT  106.452 120.091 106.47 122.521 ;
     RECT  104.796 122.521 106.47 122.791 ;
     RECT  98.784 118.895 98.802 122.819 ;
     RECT  99.615 121.055 100.566 122.909 ;
     RECT  104.472 122.791 106.47 122.909 ;
     RECT  100.98 123.061 100.998 123.101 ;
     RECT  102.132 123.061 102.15 123.215 ;
     RECT  104.796 122.909 106.47 123.421 ;
     RECT  102.312 123.331 102.33 123.485 ;
     RECT  37.8 86.881 37.818 123.719 ;
     RECT  107.424 123.331 107.442 123.755 ;
     RECT  113.616 123.691 113.634 123.871 ;
     RECT  38.88 86.341 39.006 123.899 ;
     RECT  113.58 123.871 113.634 123.961 ;
     RECT  114.372 123.871 114.39 123.961 ;
     RECT  112.68 123.835 112.698 124.123 ;
     RECT  110.415 67.531 111.33 124.141 ;
     RECT  107.604 123.835 107.658 124.219 ;
     RECT  110.415 124.141 111.654 124.231 ;
     RECT  107.604 124.219 108.234 124.259 ;
     RECT  109.872 124.231 111.654 124.267 ;
     RECT  108.036 124.259 108.234 124.411 ;
     RECT  109.872 124.267 111.726 124.411 ;
     RECT  112.608 124.123 112.698 124.411 ;
     RECT  108.036 124.411 108.378 124.529 ;
     RECT  108.036 124.529 108.126 124.565 ;
     RECT  108.108 124.565 108.126 124.601 ;
     RECT  104.796 123.421 106.686 124.637 ;
     RECT  113.58 123.961 114.39 124.645 ;
     RECT  109.224 124.411 112.698 124.681 ;
     RECT  104.796 124.637 106.614 124.709 ;
     RECT  108.972 124.681 112.698 124.709 ;
     RECT  110.304 124.709 112.698 124.771 ;
     RECT  113.58 124.645 114.498 124.771 ;
     RECT  108.972 124.709 109.458 124.799 ;
     RECT  105.015 124.709 106.614 124.835 ;
     RECT  109.224 124.799 109.458 124.835 ;
     RECT  109.26 124.835 109.458 125.105 ;
     RECT  105.015 124.835 106.074 125.141 ;
     RECT  110.304 124.771 114.498 125.221 ;
     RECT  110.304 125.221 114.534 125.311 ;
     RECT  109.44 125.105 109.458 125.609 ;
     RECT  110.304 125.311 114.606 125.609 ;
     RECT  38.88 123.899 38.898 125.753 ;
     RECT  110.304 125.609 110.754 125.753 ;
     RECT  110.304 125.753 110.697 125.761 ;
     RECT  111.564 125.609 114.606 125.761 ;
     RECT  105.015 125.141 105.786 125.789 ;
     RECT  111.564 125.761 114.642 125.851 ;
     RECT  115.815 2.413 116.097 125.851 ;
     RECT  106.596 125.761 106.614 125.951 ;
     RECT  110.016 125.761 110.697 126.185 ;
     RECT  111.564 125.851 116.097 126.725 ;
     RECT  110.415 126.185 110.697 126.805 ;
     RECT  111.564 126.725 114.966 126.805 ;
     RECT  110.415 126.805 114.966 126.959 ;
     RECT  2.415 68.144 2.697 127.187 ;
     RECT  7.815 67.289 8.097 127.187 ;
     RECT  13.215 66.509 13.497 127.187 ;
     RECT  18.615 67.829 18.897 127.187 ;
     RECT  24.015 67.805 24.297 127.187 ;
     RECT  29.415 84.335 29.697 127.187 ;
     RECT  34.815 86.459 35.097 127.187 ;
     RECT  40.215 83.795 40.497 127.187 ;
     RECT  45.615 90.029 45.897 127.187 ;
     RECT  51.015 91.373 51.297 127.187 ;
     RECT  56.415 98.105 56.697 127.187 ;
     RECT  61.815 98.141 62.097 127.187 ;
     RECT  67.215 105.395 67.497 127.187 ;
     RECT  72.288 108.869 72.897 127.187 ;
     RECT  78.015 109.715 78.297 127.187 ;
     RECT  83.415 111.581 83.697 127.187 ;
     RECT  88.815 112.991 89.097 127.187 ;
     RECT  94.215 116.699 94.497 127.187 ;
     RECT  99.615 122.909 99.897 127.187 ;
     RECT  105.015 125.789 105.297 127.187 ;
     RECT  110.415 126.959 110.697 127.187 ;
     RECT  115.815 126.725 116.097 127.187 ;
     RECT  121.215 2.413 121.497 127.187 ;
     RECT  126.615 2.413 126.897 127.187 ;
     RECT  132.015 2.413 132.297 127.187 ;
     RECT  137.415 2.413 137.697 127.187 ;
     RECT  142.815 2.413 143.097 127.187 ;
     RECT  148.215 2.413 148.497 127.187 ;
     RECT  153.615 2.413 153.897 127.187 ;
     RECT  159.015 2.413 159.297 127.187 ;
     RECT  164.415 2.413 164.697 127.187 ;
     RECT  169.815 2.413 170.097 127.187 ;
     RECT  175.215 2.413 175.497 127.187 ;
     RECT  180.615 2.413 180.897 127.187 ;
     RECT  186.015 2.413 186.297 127.187 ;
     RECT  191.415 2.413 191.697 127.187 ;
     RECT  111.456 126.959 114.966 127.229 ;
     RECT  111.456 127.229 113.778 127.265 ;
     RECT  114.84 127.229 114.966 127.265 ;
     RECT  112.176 127.265 113.778 127.409 ;
     RECT  2.415 127.187 2.505 127.457 ;
     RECT  7.815 127.187 7.905 127.457 ;
     RECT  13.215 127.187 13.305 127.457 ;
     RECT  18.615 127.187 18.705 127.457 ;
     RECT  24.015 127.187 24.105 127.457 ;
     RECT  29.415 127.187 29.505 127.457 ;
     RECT  34.815 127.187 34.905 127.457 ;
     RECT  40.215 127.187 40.305 127.457 ;
     RECT  45.615 127.187 45.705 127.457 ;
     RECT  51.015 127.187 51.105 127.457 ;
     RECT  56.415 127.187 56.505 127.457 ;
     RECT  61.815 127.187 61.905 127.457 ;
     RECT  67.215 127.187 67.305 127.457 ;
     RECT  72.288 127.187 72.705 127.457 ;
     RECT  78.015 127.187 78.105 127.457 ;
     RECT  83.415 127.187 83.505 127.457 ;
     RECT  88.815 127.187 88.905 127.457 ;
     RECT  94.215 127.187 94.305 127.457 ;
     RECT  99.615 127.187 99.705 127.457 ;
     RECT  105.015 127.187 105.105 127.457 ;
     RECT  110.415 127.187 110.505 127.457 ;
     RECT  115.815 127.187 115.905 127.457 ;
     RECT  121.215 127.187 121.305 127.457 ;
     RECT  126.615 127.187 126.705 127.457 ;
     RECT  132.015 127.187 132.105 127.457 ;
     RECT  137.415 127.187 137.505 127.457 ;
     RECT  142.815 127.187 142.905 127.457 ;
     RECT  148.215 127.187 148.305 127.457 ;
     RECT  153.615 127.187 153.705 127.457 ;
     RECT  159.015 127.187 159.105 127.457 ;
     RECT  164.415 127.187 164.505 127.457 ;
     RECT  169.815 127.187 169.905 127.457 ;
     RECT  175.215 127.187 175.305 127.457 ;
     RECT  180.615 127.187 180.705 127.457 ;
     RECT  186.015 127.187 186.105 127.457 ;
     RECT  191.415 127.187 191.505 127.457 ;
     RECT  112.176 127.409 113.31 127.613 ;
     RECT  112.176 127.613 113.274 127.661 ;
     RECT  114.948 127.265 114.966 127.661 ;
     RECT  112.176 127.661 112.446 127.709 ;
     RECT  112.176 127.709 112.338 128.813 ;
     RECT  112.32 128.813 112.338 128.861 ;
     RECT  113.256 127.661 113.274 129.403 ;
     RECT  113.256 129.403 113.346 129.485 ;
     RECT  72.288 127.457 72.306 129.581 ;
     RECT  113.328 129.485 113.346 129.581 ;
    LAYER M4 ;
     RECT  0.084 55.92 0.133 55.944 ;
     RECT  0.06 55.944 0.133 56.016 ;
     RECT  0.084 56.016 0.133 56.04 ;
     RECT  0.06 56.04 0.133 56.112 ;
     RECT  0.084 56.112 0.133 56.136 ;
     RECT  0.06 56.136 0.133 56.208 ;
     RECT  0.084 56.208 0.133 56.232 ;
     RECT  0.06 56.232 0.133 56.304 ;
     RECT  0.084 56.304 0.133 56.328 ;
     RECT  0.06 56.328 0.133 56.4 ;
     RECT  0.084 56.4 0.133 56.424 ;
     RECT  0.06 56.424 0.133 56.496 ;
     RECT  0.084 56.496 0.133 56.52 ;
     RECT  0.06 56.52 0.133 56.592 ;
     RECT  0.084 56.592 0.133 56.616 ;
     RECT  0.06 56.616 0.133 56.688 ;
     RECT  0.084 56.688 0.133 56.712 ;
     RECT  0.06 56.712 0.133 56.784 ;
     RECT  0.084 56.784 0.133 56.808 ;
     RECT  0.06 56.808 0.133 56.88 ;
     RECT  0.084 56.88 0.133 56.904 ;
     RECT  0.06 56.904 0.133 56.976 ;
     RECT  0.084 56.976 0.133 57 ;
     RECT  0.06 57 0.133 57.072 ;
     RECT  0.084 57.072 0.133 57.096 ;
     RECT  0.06 57.096 0.133 57.168 ;
     RECT  0.084 57.168 0.133 57.192 ;
     RECT  0.06 57.192 0.133 57.264 ;
     RECT  0.084 57.264 0.133 57.288 ;
     RECT  0.06 57.288 0.133 57.36 ;
     RECT  0.084 57.36 0.133 57.384 ;
     RECT  0.06 57.384 0.133 57.456 ;
     RECT  0.084 57.456 0.133 57.48 ;
     RECT  0.06 57.48 0.133 57.552 ;
     RECT  0.084 57.552 0.133 57.576 ;
     RECT  0.06 57.576 0.133 57.648 ;
     RECT  0.084 57.648 0.133 57.672 ;
     RECT  0.06 57.672 0.133 57.744 ;
     RECT  0.084 57.744 0.133 57.768 ;
     RECT  0.06 57.768 0.133 57.84 ;
     RECT  0.084 57.84 0.133 57.864 ;
     RECT  0.06 57.864 0.133 57.936 ;
     RECT  0.084 57.936 0.133 57.96 ;
     RECT  0.06 57.96 0.133 58.032 ;
     RECT  0.084 58.032 0.133 58.056 ;
     RECT  0.06 58.056 0.133 58.128 ;
     RECT  0.084 58.128 0.133 58.152 ;
     RECT  0.06 58.152 0.133 58.224 ;
     RECT  0.084 58.224 0.133 58.248 ;
     RECT  0.06 58.248 0.133 58.32 ;
     RECT  0.084 58.32 0.133 58.344 ;
     RECT  0.06 58.344 0.133 58.416 ;
     RECT  0.084 58.416 0.133 58.44 ;
     RECT  0.06 58.44 0.133 58.512 ;
     RECT  0.084 58.512 0.133 58.536 ;
     RECT  0.06 58.536 0.133 58.608 ;
     RECT  0.084 58.608 0.133 58.632 ;
     RECT  0.06 58.632 0.133 58.704 ;
     RECT  0.084 58.704 0.133 58.728 ;
     RECT  0.06 58.728 0.133 58.8 ;
     RECT  0.084 58.8 0.133 58.824 ;
     RECT  0.06 58.824 0.133 58.896 ;
     RECT  0.084 58.896 0.133 58.92 ;
     RECT  0.06 58.92 0.133 58.992 ;
     RECT  0.084 58.992 0.133 59.016 ;
     RECT  0.06 59.016 0.133 59.088 ;
     RECT  0.084 59.088 0.133 59.112 ;
     RECT  0.06 59.112 0.133 59.184 ;
     RECT  0.084 59.184 0.133 59.208 ;
     RECT  0.06 59.208 0.133 59.28 ;
     RECT  0.084 59.28 0.133 59.304 ;
     RECT  0.06 59.304 0.133 59.376 ;
     RECT  0.084 59.376 0.133 59.4 ;
     RECT  0.06 59.4 0.133 59.472 ;
     RECT  0.084 59.472 0.133 59.496 ;
     RECT  0.06 59.496 0.133 59.568 ;
     RECT  0.084 59.568 0.133 59.592 ;
     RECT  0.06 59.592 0.133 59.664 ;
     RECT  0.084 59.664 0.133 59.688 ;
     RECT  0.06 59.688 0.133 59.76 ;
     RECT  0.084 59.76 0.133 59.784 ;
     RECT  0.06 59.784 0.133 59.856 ;
     RECT  0.084 59.856 0.133 59.88 ;
     RECT  0.06 59.88 0.133 59.952 ;
     RECT  0.084 59.952 0.133 59.976 ;
     RECT  0.06 59.976 0.133 60.048 ;
     RECT  0.084 60.048 0.133 60.072 ;
     RECT  0.06 60.072 0.133 60.144 ;
     RECT  0.084 60.144 0.133 60.168 ;
     RECT  0.06 60.168 0.133 60.24 ;
     RECT  0.084 60.24 0.133 60.264 ;
     RECT  0.06 60.264 0.133 60.336 ;
     RECT  0.084 60.336 0.133 60.36 ;
     RECT  0.06 60.36 0.133 60.432 ;
     RECT  0.084 60.432 0.133 60.456 ;
     RECT  0.06 60.456 0.133 60.528 ;
     RECT  0.084 60.528 0.133 60.552 ;
     RECT  0.06 60.552 0.133 60.624 ;
     RECT  0.084 60.624 0.133 60.648 ;
     RECT  0.06 60.648 0.133 60.72 ;
     RECT  0.084 60.72 0.133 60.744 ;
     RECT  0.06 60.744 0.133 60.816 ;
     RECT  0.084 60.816 0.133 60.84 ;
     RECT  0.06 60.84 0.133 60.912 ;
     RECT  0.084 60.912 0.133 60.936 ;
     RECT  0.06 60.936 0.133 61.008 ;
     RECT  0.084 61.008 0.133 61.032 ;
     RECT  0.06 61.032 0.133 61.104 ;
     RECT  0.084 61.104 0.133 61.128 ;
     RECT  0.06 61.128 0.133 61.2 ;
     RECT  0.084 61.2 0.133 61.224 ;
     RECT  0.06 61.224 0.133 61.296 ;
     RECT  0.084 61.296 0.133 61.32 ;
     RECT  0.06 61.32 0.133 61.392 ;
     RECT  0.084 61.392 0.133 61.416 ;
     RECT  0.06 61.416 0.133 61.488 ;
     RECT  0.084 61.488 0.133 61.512 ;
     RECT  0.06 61.512 0.133 61.584 ;
     RECT  0.084 61.584 0.133 61.608 ;
     RECT  0.06 61.608 0.133 61.68 ;
     RECT  0.084 61.68 0.133 61.704 ;
     RECT  0.06 61.704 0.133 61.776 ;
     RECT  0.084 61.776 0.133 61.8 ;
     RECT  0.06 61.8 0.133 61.872 ;
     RECT  0.084 61.872 0.133 61.896 ;
     RECT  0.06 61.896 0.133 61.968 ;
     RECT  0.084 61.968 0.133 61.992 ;
     RECT  0.06 61.992 0.133 62.064 ;
     RECT  0.084 62.064 0.133 62.088 ;
     RECT  0.06 62.088 0.133 62.16 ;
     RECT  0.084 62.16 0.133 62.184 ;
     RECT  0.06 62.184 0.133 62.256 ;
     RECT  0.084 62.256 0.133 62.28 ;
     RECT  0.06 62.28 0.133 62.352 ;
     RECT  0.084 62.352 0.133 62.376 ;
     RECT  0.06 62.376 0.133 62.448 ;
     RECT  0.084 62.448 0.133 62.472 ;
     RECT  0.06 62.472 0.133 62.544 ;
     RECT  0.084 62.544 0.133 62.568 ;
     RECT  0.06 62.568 0.133 62.64 ;
     RECT  0.084 62.64 0.133 62.664 ;
     RECT  0.06 62.664 0.133 62.736 ;
     RECT  0.084 62.736 0.133 62.76 ;
     RECT  0.06 62.76 0.133 62.832 ;
     RECT  0.084 62.832 0.133 62.856 ;
     RECT  0.06 62.856 0.133 62.928 ;
     RECT  0.084 62.928 0.133 62.952 ;
     RECT  0.06 62.952 0.133 63.024 ;
     RECT  0.084 63.024 0.133 63.048 ;
     RECT  0.06 63.048 0.133 63.12 ;
     RECT  0.084 63.12 0.133 63.144 ;
     RECT  0.06 63.144 0.133 63.216 ;
     RECT  0.084 63.216 0.133 63.24 ;
     RECT  0.06 63.24 0.133 63.312 ;
     RECT  0.084 63.312 0.133 63.336 ;
     RECT  0.06 63.336 0.133 63.408 ;
     RECT  0.084 63.408 0.133 63.432 ;
     RECT  0.06 63.432 0.133 63.504 ;
     RECT  0.084 63.504 0.133 63.528 ;
     RECT  0.06 63.528 0.133 63.6 ;
     RECT  0.084 63.6 0.133 63.624 ;
     RECT  0.06 63.624 0.133 63.696 ;
     RECT  0.084 63.696 0.133 63.72 ;
     RECT  0.06 63.72 0.133 63.792 ;
     RECT  0.084 63.792 0.133 63.816 ;
     RECT  0.06 63.816 0.133 63.888 ;
     RECT  0.084 63.888 0.133 63.912 ;
     RECT  0.06 63.912 0.133 63.984 ;
     RECT  0.084 63.984 0.133 64.008 ;
     RECT  0.06 64.008 0.133 64.08 ;
     RECT  0.084 64.08 0.133 64.104 ;
     RECT  0.06 64.104 0.133 64.176 ;
     RECT  0.084 64.176 0.133 64.2 ;
     RECT  0.06 64.2 0.133 64.272 ;
     RECT  0.084 64.272 0.133 64.296 ;
     RECT  0.06 64.296 0.133 64.368 ;
     RECT  0.084 64.368 0.133 64.392 ;
     RECT  0.06 64.392 0.133 64.464 ;
     RECT  0.084 64.464 0.133 64.488 ;
     RECT  0.06 64.488 0.133 64.56 ;
     RECT  0.084 64.56 0.133 64.584 ;
     RECT  0.133 55.92 0.137 64.632 ;
     RECT  0.137 56.016 0.205 64.632 ;
     RECT  0.205 56.016 2.408 64.728 ;
     RECT  2.408 2.148 2.512 127.452 ;
     RECT  2.512 2.418 2.704 127.182 ;
     RECT  2.704 56.016 2.88 65.784 ;
     RECT  2.88 56.016 2.909 64.728 ;
     RECT  2.909 56.016 2.981 64.392 ;
     RECT  2.981 56.064 3.233 64.392 ;
     RECT  3.233 56.592 3.949 64.392 ;
     RECT  2.88 65.76 3.949 65.784 ;
     RECT  3.949 65.664 4.309 65.784 ;
     RECT  3.949 56.592 4.957 64.44 ;
     RECT  4.309 65.568 4.957 65.784 ;
     RECT  4.957 56.592 4.993 65.784 ;
     RECT  4.993 56.544 5.177 65.784 ;
     RECT  5.177 60.96 5.315 65.784 ;
     RECT  5.315 65.568 5.533 65.784 ;
     RECT  5.315 60.96 5.573 64.584 ;
     RECT  5.573 60.96 5.681 64.44 ;
     RECT  5.533 65.568 5.699 66.168 ;
     RECT  5.177 56.544 6.037 59.784 ;
     RECT  5.681 60.96 6.257 64.344 ;
     RECT  5.699 66.144 6.289 66.168 ;
     RECT  6.037 55.824 6.437 59.784 ;
     RECT  6.257 63.696 6.437 64.344 ;
     RECT  6.437 56.256 6.581 59.784 ;
     RECT  6.257 60.96 6.617 62.472 ;
     RECT  6.581 56.304 7.009 59.784 ;
     RECT  6.617 60.96 7.009 62.424 ;
     RECT  6.289 66.144 7.189 66.264 ;
     RECT  6.437 63.792 7.693 64.344 ;
     RECT  7.009 56.304 7.729 62.424 ;
     RECT  7.693 63.6 7.729 64.344 ;
     RECT  7.729 56.304 7.808 64.344 ;
     RECT  7.189 65.856 7.808 66.264 ;
     RECT  7.808 2.148 7.912 127.452 ;
     RECT  7.912 2.418 8.104 127.182 ;
     RECT  8.104 56.208 8.453 64.104 ;
     RECT  8.453 58.656 8.957 64.104 ;
     RECT  8.104 65.568 9.385 66.504 ;
     RECT  8.957 58.656 9.389 63.816 ;
     RECT  8.453 56.208 9.673 57.528 ;
     RECT  9.389 58.656 9.673 63.672 ;
     RECT  9.385 65.136 9.817 66.504 ;
     RECT  9.673 56.208 10.933 63.672 ;
     RECT  10.933 56.208 11.225 63.864 ;
     RECT  9.817 65.088 11.293 66.504 ;
     RECT  11.225 56.304 11.315 63.864 ;
     RECT  11.293 64.944 11.459 66.504 ;
     RECT  11.459 65.568 11.585 66.504 ;
     RECT  11.315 56.304 11.837 63.624 ;
     RECT  11.837 63.552 12.517 63.624 ;
     RECT  11.585 65.664 12.901 66.504 ;
     RECT  11.837 56.304 13.165 62.568 ;
     RECT  12.517 63.552 13.165 63.816 ;
     RECT  13.165 56.304 13.208 63.816 ;
     RECT  12.901 64.896 13.208 66.504 ;
     RECT  13.208 2.148 13.312 127.452 ;
     RECT  13.312 2.418 13.504 127.182 ;
     RECT  13.504 56.304 13.673 66.504 ;
     RECT  13.673 56.304 13.709 65.976 ;
     RECT  13.709 60.624 13.781 65.976 ;
     RECT  13.709 56.304 13.889 59.592 ;
     RECT  13.781 65.52 14.785 65.976 ;
     RECT  13.781 60.624 14.969 64.44 ;
     RECT  14.969 63.552 15.001 64.44 ;
     RECT  14.785 65.52 15.001 66.024 ;
     RECT  15.001 63.552 15.041 66.024 ;
     RECT  15.041 63.552 15.113 65.976 ;
     RECT  13.889 56.88 15.349 59.592 ;
     RECT  14.969 60.624 15.349 62.568 ;
     RECT  15.001 67.2 15.685 67.224 ;
     RECT  15.349 56.88 15.689 62.568 ;
     RECT  15.689 56.88 15.721 59.592 ;
     RECT  15.113 63.552 15.761 65.688 ;
     RECT  15.689 60.624 16.009 62.568 ;
     RECT  15.761 63.552 16.009 64.44 ;
     RECT  15.721 56.544 16.553 59.592 ;
     RECT  15.761 65.664 16.829 65.688 ;
     RECT  16.829 65.664 16.837 66.12 ;
     RECT  15.685 67.2 16.837 67.272 ;
     RECT  16.837 65.664 16.913 67.272 ;
     RECT  16.553 56.544 17.237 57.576 ;
     RECT  16.009 60.624 17.345 64.44 ;
     RECT  16.553 58.992 17.585 59.592 ;
     RECT  17.345 60.624 17.585 63.624 ;
     RECT  17.237 57.072 17.809 57.576 ;
     RECT  17.585 58.992 17.809 63.624 ;
     RECT  16.913 66.768 17.809 67.272 ;
     RECT  17.809 66.768 18.469 67.32 ;
     RECT  17.809 57.072 18.608 63.624 ;
     RECT  16.913 65.664 18.608 65.688 ;
     RECT  18.469 66.768 18.608 67.416 ;
     RECT  18.608 2.148 18.712 127.452 ;
     RECT  18.712 2.418 18.904 127.182 ;
     RECT  18.904 65.664 19.043 65.688 ;
     RECT  18.904 67.056 19.325 67.32 ;
     RECT  19.325 67.248 19.397 67.32 ;
     RECT  18.904 58.704 19.613 64.536 ;
     RECT  18.904 56.064 19.901 57.72 ;
     RECT  19.901 56.352 20.113 57.72 ;
     RECT  19.613 58.704 20.113 63.816 ;
     RECT  20.113 56.352 20.189 63.816 ;
     RECT  20.189 57.072 20.339 63.816 ;
     RECT  20.339 57.072 20.38 59.256 ;
     RECT  19.397 67.296 20.797 67.32 ;
     RECT  20.797 67.296 20.837 67.704 ;
     RECT  21.517 65.664 21.788 65.688 ;
     RECT  21.788 64.848 21.875 65.688 ;
     RECT  20.38 57.072 21.913 59.016 ;
     RECT  20.339 60.576 21.913 63.816 ;
     RECT  20.837 67.68 21.923 67.704 ;
     RECT  21.913 57.072 22.405 63.816 ;
     RECT  22.405 56.928 22.493 63.816 ;
     RECT  22.561 67.296 22.745 67.32 ;
     RECT  21.875 64.944 22.777 65.688 ;
     RECT  22.777 64.944 22.849 65.832 ;
     RECT  22.493 57.072 23.317 63.816 ;
     RECT  22.849 64.944 23.317 67.128 ;
     RECT  23.317 57.072 24.008 67.128 ;
     RECT  21.877 70.56 24.008 70.584 ;
     RECT  24.008 2.148 24.112 127.452 ;
     RECT  24.112 2.418 24.304 127.182 ;
     RECT  24.304 57.072 24.761 64.344 ;
     RECT  24.761 58.128 25.085 64.344 ;
     RECT  24.304 65.664 25.139 66.648 ;
     RECT  25.085 60.048 25.589 64.344 ;
     RECT  25.085 58.128 25.667 59.016 ;
     RECT  25.589 60.048 25.913 63.816 ;
     RECT  25.667 58.944 26.089 59.016 ;
     RECT  26.089 58.944 26.129 59.304 ;
     RECT  25.913 60.576 26.165 63.816 ;
     RECT  24.304 67.776 26.197 67.8 ;
     RECT  26.197 67.536 26.265 67.8 ;
     RECT  24.761 57.072 26.489 57.096 ;
     RECT  25.945 65.52 26.557 65.544 ;
     RECT  26.557 65.52 26.777 66.504 ;
     RECT  26.777 65.52 26.921 65.544 ;
     RECT  26.129 58.992 27.097 59.304 ;
     RECT  26.165 60.576 27.097 63.768 ;
     RECT  26.265 67.536 27.097 67.56 ;
     RECT  27.097 67.248 27.137 67.56 ;
     RECT  24.304 70.56 27.173 70.584 ;
     RECT  27.097 58.992 27.425 63.768 ;
     RECT  27.425 59.04 27.925 63.768 ;
     RECT  27.781 66.24 27.961 66.264 ;
     RECT  27.137 67.248 27.961 67.272 ;
     RECT  27.884 68.256 27.971 68.28 ;
     RECT  27.961 66.24 28.045 67.272 ;
     RECT  27.925 59.04 28.073 63.816 ;
     RECT  28.073 60.624 28.289 63.816 ;
     RECT  28.073 59.04 28.325 59.064 ;
     RECT  28.045 66.24 28.753 66.264 ;
     RECT  28.289 63.264 28.897 63.816 ;
     RECT  27.961 78.624 28.997 78.648 ;
     RECT  27.925 80.64 29.005 80.664 ;
     RECT  27.637 82.032 29.005 82.056 ;
     RECT  29.005 80.64 29.269 82.056 ;
     RECT  29.269 80.64 29.401 82.296 ;
     RECT  28.289 60.624 29.408 61.992 ;
     RECT  28.897 63.264 29.408 63.864 ;
     RECT  28.753 65.52 29.408 66.264 ;
     RECT  28.045 67.248 29.408 67.272 ;
     RECT  28.997 78.624 29.408 79.272 ;
     RECT  29.401 80.64 29.408 83.256 ;
     RECT  29.408 2.148 29.512 127.452 ;
     RECT  29.512 2.418 29.704 127.182 ;
     RECT  29.704 79.68 29.765 83.832 ;
     RECT  29.704 68.208 29.843 68.232 ;
     RECT  29.765 82.512 29.843 83.832 ;
     RECT  29.704 77.952 29.884 78.648 ;
     RECT  29.843 82.512 29.891 82.536 ;
     RECT  29.843 83.808 29.917 83.832 ;
     RECT  29.704 63.792 30.089 63.864 ;
     RECT  29.704 60.864 30.305 62.088 ;
     RECT  29.704 65.52 30.413 65.544 ;
     RECT  29.765 79.68 31.061 80.664 ;
     RECT  30.877 82.656 31.309 82.68 ;
     RECT  31.309 82.656 31.349 83.208 ;
     RECT  30.305 60.864 31.628 60.888 ;
     RECT  30.305 61.92 31.628 62.088 ;
     RECT  31.628 60.864 31.669 62.088 ;
     RECT  31.669 60.864 31.709 62.184 ;
     RECT  31.709 60.96 31.715 62.184 ;
     RECT  31.715 61.92 31.889 62.184 ;
     RECT  31.349 83.184 32.105 83.208 ;
     RECT  29.884 78.624 32.828 78.648 ;
     RECT  31.889 61.92 32.857 61.992 ;
     RECT  32.828 78.624 32.915 79.08 ;
     RECT  32.857 61.92 33.113 62.664 ;
     RECT  33.181 82.608 33.205 82.632 ;
     RECT  32.533 83.76 33.205 83.784 ;
     RECT  33.205 82.608 33.265 83.784 ;
     RECT  32.641 85.632 33.829 85.656 ;
     RECT  33.113 61.92 33.937 61.992 ;
     RECT  33.265 82.944 33.937 83.784 ;
     RECT  33.829 84.816 33.937 85.656 ;
     RECT  32.915 78.624 34.225 78.648 ;
     RECT  33.937 61.44 34.808 61.992 ;
     RECT  30.089 63.792 34.808 63.816 ;
     RECT  29.704 69.456 34.808 69.48 ;
     RECT  34.117 76.32 34.808 76.344 ;
     RECT  34.225 78.624 34.808 78.696 ;
     RECT  31.061 80.64 34.808 80.664 ;
     RECT  33.937 82.944 34.808 85.656 ;
     RECT  34.808 2.148 34.912 127.452 ;
     RECT  34.912 2.418 35.104 127.182 ;
     RECT  35.104 76.32 35.363 77.352 ;
     RECT  35.104 78.672 35.363 79.08 ;
     RECT  35.363 79.056 35.507 79.08 ;
     RECT  35.104 80.544 35.507 81.048 ;
     RECT  35.363 76.896 35.561 77.352 ;
     RECT  35.104 86.016 35.993 86.232 ;
     RECT  35.104 61.92 36.133 62.184 ;
     RECT  35.104 63.216 36.133 63.24 ;
     RECT  35.104 84.288 36.421 85.032 ;
     RECT  35.993 86.016 36.421 86.04 ;
     RECT  36.421 84.288 36.461 86.04 ;
     RECT  36.461 85.488 36.713 86.04 ;
     RECT  35.561 77.328 36.853 77.352 ;
     RECT  36.133 61.92 36.857 63.24 ;
     RECT  36.853 76.368 37.253 77.352 ;
     RECT  36.857 62.256 37.289 63.24 ;
     RECT  37.289 63.216 37.433 63.24 ;
     RECT  35.507 80.544 39.253 80.664 ;
     RECT  37.753 82.944 39.661 82.968 ;
     RECT  37.253 76.368 40.208 76.392 ;
     RECT  39.212 77.424 40.208 77.448 ;
     RECT  39.253 80.256 40.208 80.664 ;
     RECT  39.661 82.944 40.208 83.064 ;
     RECT  36.461 84.288 40.208 84.312 ;
     RECT  40.208 2.148 40.312 127.452 ;
     RECT  40.312 2.418 40.504 127.182 ;
     RECT  40.504 83.04 40.953 83.064 ;
     RECT  40.504 80.256 41.861 81.48 ;
     RECT  41.861 80.256 43.441 80.664 ;
     RECT  40.504 84.288 43.729 84.312 ;
     RECT  43.441 80.256 45.608 80.856 ;
     RECT  43.729 84.144 45.608 84.312 ;
     RECT  45.608 2.148 45.712 127.452 ;
     RECT  45.712 2.418 45.904 127.182 ;
     RECT  45.904 84.144 46.433 85.128 ;
     RECT  46.433 84.288 47.653 85.128 ;
     RECT  47.653 84.288 47.693 85.512 ;
     RECT  47.693 85.488 48.332 85.512 ;
     RECT  48.332 85.488 48.377 86.04 ;
     RECT  48.377 86.016 48.419 86.04 ;
     RECT  45.904 80.256 48.515 80.856 ;
     RECT  48.469 82.08 48.524 82.104 ;
     RECT  48.524 82.08 48.629 82.632 ;
     RECT  48.373 88.272 48.949 88.296 ;
     RECT  47.693 84.288 48.995 84.312 ;
     RECT  45.904 90 48.997 90.024 ;
     RECT  48.913 82.752 49.043 82.776 ;
     RECT  48.949 87.984 49.043 88.296 ;
     RECT  48.997 89.28 49.097 90.024 ;
     RECT  49.309 87.792 50.197 87.816 ;
     RECT  48.515 80.832 51.008 80.856 ;
     RECT  48.997 84.576 51.008 84.6 ;
     RECT  50.197 86.88 51.008 87.816 ;
     RECT  49.097 89.28 51.008 89.304 ;
     RECT  50.869 91.344 51.008 91.368 ;
     RECT  48.949 96.576 51.008 96.6 ;
     RECT  51.008 2.148 51.112 127.452 ;
     RECT  51.112 2.418 51.304 127.182 ;
     RECT  53.053 85.632 53.084 85.656 ;
     RECT  51.304 91.344 53.084 91.368 ;
     RECT  53.084 85.584 53.171 85.656 ;
     RECT  53.084 91.344 53.171 91.848 ;
     RECT  53.125 90 53.453 90.024 ;
     RECT  51.304 84.576 53.561 84.6 ;
     RECT  53.171 85.632 55.1 85.656 ;
     RECT  55.1 85.44 55.141 85.656 ;
     RECT  55.141 85.44 55.187 86.52 ;
     RECT  51.304 80.832 56.408 80.856 ;
     RECT  55.187 86.496 56.408 86.52 ;
     RECT  51.304 96.576 56.408 96.6 ;
     RECT  56.408 2.148 56.512 127.452 ;
     RECT  56.512 2.418 56.704 127.182 ;
     RECT  59.713 91.344 61.333 91.368 ;
     RECT  56.704 80.832 61.808 80.856 ;
     RECT  61.333 91.344 61.808 91.656 ;
     RECT  56.704 96.576 61.808 96.6 ;
     RECT  61.801 98.112 61.808 98.136 ;
     RECT  61.333 103.2 61.808 103.224 ;
     RECT  61.808 2.148 61.912 127.452 ;
     RECT  61.912 2.418 62.104 127.182 ;
     RECT  62.104 94.56 62.317 94.584 ;
     RECT  62.104 90.912 62.627 91.368 ;
     RECT  62.104 92.64 62.668 92.952 ;
     RECT  62.104 95.76 63.829 96.6 ;
     RECT  63.829 95.52 63.875 96.6 ;
     RECT  62.104 98.112 64.069 98.136 ;
     RECT  64.069 98.112 64.115 98.616 ;
     RECT  63.875 95.52 64.145 95.544 ;
     RECT  63.875 96.576 65.653 96.6 ;
     RECT  62.668 92.928 65.721 92.952 ;
     RECT  64.115 98.592 66.293 98.616 ;
     RECT  66.293 98.592 66.337 99.192 ;
     RECT  62.104 103.2 66.589 103.224 ;
     RECT  62.627 91.344 67.208 91.368 ;
     RECT  65.653 96.576 67.208 96.744 ;
     RECT  66.337 98.592 67.208 99.768 ;
     RECT  66.589 103.008 67.208 103.224 ;
     RECT  67.208 2.148 67.312 127.452 ;
     RECT  67.312 2.418 67.504 127.182 ;
     RECT  67.504 98.448 67.859 98.472 ;
     RECT  67.504 99.696 67.859 99.768 ;
     RECT  67.859 99.744 67.925 99.768 ;
     RECT  67.504 102.624 70.501 103.224 ;
     RECT  67.504 96.576 70.517 96.744 ;
     RECT  70.501 102.624 72.469 103.32 ;
     RECT  67.504 91.344 72.608 91.368 ;
     RECT  70.517 96.576 72.608 96.6 ;
     RECT  72.469 102.192 72.608 103.32 ;
     RECT  72.469 108.336 72.608 108.36 ;
     RECT  72.608 2.148 72.712 127.452 ;
     RECT  72.712 2.418 72.904 127.182 ;
     RECT  74.285 98.64 74.293 98.664 ;
     RECT  74.293 98.352 74.3 98.664 ;
     RECT  72.904 96.576 74.339 96.6 ;
     RECT  74.3 98.352 74.387 98.76 ;
     RECT  72.904 103.2 74.693 103.32 ;
     RECT  74.387 98.352 74.801 98.376 ;
     RECT  72.904 102.096 76.025 102.12 ;
     RECT  74.693 103.296 76.417 103.32 ;
     RECT  76.417 103.2 76.457 103.32 ;
     RECT  72.904 91.344 78.008 91.368 ;
     RECT  73.969 99.936 78.008 99.96 ;
     RECT  76.457 103.2 78.008 103.224 ;
     RECT  76.057 108.864 78.008 108.888 ;
     RECT  78.008 2.148 78.112 127.452 ;
     RECT  78.112 2.418 78.304 127.182 ;
     RECT  78.304 108.864 78.467 109.368 ;
     RECT  78.467 109.344 78.481 109.368 ;
     RECT  78.304 107.136 78.509 107.16 ;
     RECT  78.304 110.496 81.685 110.52 ;
     RECT  81.685 110.496 81.713 111.432 ;
     RECT  78.304 103.2 81.731 103.224 ;
     RECT  81.644 109.344 81.731 109.368 ;
     RECT  82.213 107.712 83.221 107.736 ;
     RECT  81.961 110.016 83.221 110.04 ;
     RECT  78.304 91.344 83.408 91.368 ;
     RECT  83.221 107.712 83.408 108.36 ;
     RECT  83.221 109.728 83.408 110.04 ;
     RECT  81.713 111.408 83.408 111.432 ;
     RECT  83.408 2.148 83.512 127.452 ;
     RECT  83.512 2.418 83.704 127.182 ;
     RECT  83.704 111.408 83.801 111.576 ;
     RECT  83.704 109.728 84.697 109.752 ;
     RECT  84.697 109.728 84.737 109.848 ;
     RECT  85.532 108.48 85.619 108.504 ;
     RECT  83.801 111.552 85.916 111.576 ;
     RECT  85.633 112.656 85.916 112.68 ;
     RECT  84.737 109.824 86.003 109.848 ;
     RECT  85.916 111.552 86.003 112.68 ;
     RECT  86.003 112.656 87.833 112.68 ;
     RECT  83.704 91.344 88.808 91.368 ;
     RECT  87.469 109.248 88.808 109.272 ;
     RECT  86.003 111.552 88.808 111.576 ;
     RECT  88.808 2.148 88.912 127.452 ;
     RECT  88.912 2.418 89.104 127.182 ;
     RECT  89.104 109.248 90.097 109.272 ;
     RECT  90.097 109.248 90.137 110.088 ;
     RECT  90.137 110.064 91.141 110.088 ;
     RECT  91.069 107.712 91.187 107.736 ;
     RECT  91.141 109.92 91.189 110.088 ;
     RECT  89.104 111.552 91.189 111.576 ;
     RECT  91.189 109.92 91.228 110.52 ;
     RECT  91.228 110.064 91.281 110.52 ;
     RECT  91.281 110.496 91.757 110.52 ;
     RECT  90.709 112.848 92.533 112.872 ;
     RECT  92.533 112.848 92.579 113.448 ;
     RECT  92.579 113.424 92.581 113.448 ;
     RECT  92.581 113.424 92.621 113.976 ;
     RECT  92.621 113.952 92.665 113.976 ;
     RECT  89.104 91.344 94.208 91.368 ;
     RECT  91.189 111.552 94.208 111.816 ;
     RECT  92.365 115.632 94.208 115.656 ;
     RECT  94.208 2.148 94.312 127.452 ;
     RECT  94.312 2.418 94.504 127.182 ;
     RECT  95.989 113.664 96.001 113.688 ;
     RECT  94.504 111.552 96.035 111.768 ;
     RECT  96.001 113.664 96.076 113.976 ;
     RECT  96.076 113.952 98.588 113.976 ;
     RECT  96.035 111.552 98.593 111.576 ;
     RECT  94.504 115.632 98.629 115.656 ;
     RECT  98.593 111.552 98.633 111.672 ;
     RECT  94.504 91.344 99.608 91.368 ;
     RECT  98.633 111.648 99.608 111.672 ;
     RECT  98.588 113.952 99.608 114.552 ;
     RECT  98.629 115.632 99.608 116.184 ;
     RECT  98.053 118.608 99.608 118.632 ;
     RECT  99.608 2.148 99.712 127.452 ;
     RECT  99.712 2.418 99.904 127.182 ;
     RECT  99.904 115.632 100.019 116.184 ;
     RECT  99.904 117.216 100.019 117.24 ;
     RECT  99.904 118.608 100.019 118.632 ;
     RECT  100.94 123.072 100.981 123.096 ;
     RECT  100.981 123.072 101.027 123.384 ;
     RECT  99.904 120.576 101.324 120.6 ;
     RECT  101.027 123.36 101.365 123.384 ;
     RECT  101.324 120.576 101.369 120.696 ;
     RECT  99.904 111.648 101.411 111.672 ;
     RECT  101.369 120.672 101.411 120.696 ;
     RECT  100.019 116.16 103.133 116.184 ;
     RECT  101.365 123.36 104.869 124.152 ;
     RECT  103.489 63.504 105.008 63.528 ;
     RECT  99.904 91.344 105.008 91.368 ;
     RECT  104.869 123.264 105.008 124.488 ;
     RECT  105.008 2.148 105.112 127.452 ;
     RECT  105.112 2.418 105.304 127.182 ;
     RECT  105.304 123.264 106.405 124.152 ;
     RECT  106.405 123.264 106.509 124.248 ;
     RECT  105.304 63.504 107.413 63.912 ;
     RECT  107.413 63.36 109.465 63.912 ;
     RECT  106.509 124.128 110.293 124.248 ;
     RECT  109.465 63.312 110.408 63.912 ;
     RECT  105.304 91.344 110.408 91.368 ;
     RECT  110.293 124.128 110.408 125.736 ;
     RECT  110.408 2.148 110.512 127.452 ;
     RECT  110.512 2.418 110.704 127.182 ;
     RECT  110.704 124.128 111.697 124.296 ;
     RECT  72.277 129.552 112.165 129.576 ;
     RECT  110.704 91.344 112.307 91.368 ;
     RECT  112.165 128.784 112.403 129.576 ;
     RECT  111.697 124.128 112.453 125.64 ;
     RECT  112.403 128.832 112.499 129.576 ;
     RECT  112.417 127.68 112.549 127.704 ;
     RECT  112.453 124.128 112.597 126.408 ;
     RECT  112.597 124.128 112.637 126.504 ;
     RECT  112.549 127.632 112.691 127.704 ;
     RECT  112.637 124.656 112.7 126.504 ;
     RECT  112.691 127.632 112.7 127.656 ;
     RECT  112.7 124.656 112.709 127.656 ;
     RECT  112.709 125.328 112.787 127.656 ;
     RECT  112.787 127.584 113.321 127.656 ;
     RECT  112.499 129.408 113.357 129.576 ;
     RECT  113.357 129.408 113.401 129.432 ;
     RECT  112.787 125.328 113.429 126.504 ;
     RECT  113.429 125.328 113.609 125.928 ;
     RECT  113.609 125.904 114.437 125.928 ;
     RECT  113.321 127.632 114.977 127.656 ;
     RECT  110.704 63.312 115.808 63.912 ;
     RECT  115.808 2.148 115.912 127.452 ;
     RECT  115.912 2.418 116.104 127.182 ;
     RECT  116.104 63.312 121.208 63.912 ;
     RECT  121.208 2.148 121.312 127.452 ;
     RECT  121.312 2.418 121.504 127.182 ;
     RECT  121.504 63.312 126.608 63.912 ;
     RECT  126.608 2.148 126.712 127.452 ;
     RECT  126.712 2.418 126.904 127.182 ;
     RECT  126.904 63.312 132.008 63.912 ;
     RECT  132.008 2.148 132.112 127.452 ;
     RECT  132.112 2.418 132.304 127.182 ;
     RECT  132.304 63.312 137.408 63.912 ;
     RECT  137.408 2.148 137.512 127.452 ;
     RECT  137.512 2.418 137.704 127.182 ;
     RECT  137.704 63.312 142.808 63.912 ;
     RECT  142.808 2.148 142.912 127.452 ;
     RECT  142.912 2.418 143.104 127.182 ;
     RECT  143.104 63.312 148.208 63.912 ;
     RECT  148.208 2.148 148.312 127.452 ;
     RECT  148.312 2.418 148.504 127.182 ;
     RECT  148.504 63.312 153.608 63.912 ;
     RECT  153.608 2.148 153.712 127.452 ;
     RECT  153.712 2.418 153.904 127.182 ;
     RECT  153.904 63.312 159.008 63.912 ;
     RECT  159.008 2.148 159.112 127.452 ;
     RECT  159.112 2.418 159.304 127.182 ;
     RECT  159.304 63.312 164.408 63.912 ;
     RECT  164.408 2.148 164.512 127.452 ;
     RECT  164.512 2.418 164.704 127.182 ;
     RECT  164.704 63.312 169.808 63.912 ;
     RECT  169.808 2.148 169.912 127.452 ;
     RECT  169.912 2.418 170.104 127.182 ;
     RECT  170.104 63.312 175.208 63.912 ;
     RECT  175.208 2.148 175.312 127.452 ;
     RECT  175.312 2.418 175.504 127.182 ;
     RECT  175.504 63.312 180.608 63.912 ;
     RECT  180.608 2.148 180.712 127.452 ;
     RECT  180.712 2.418 180.904 127.182 ;
     RECT  180.904 63.312 186.008 63.912 ;
     RECT  186.008 2.148 186.112 127.452 ;
     RECT  186.112 2.418 186.304 127.182 ;
     RECT  186.304 63.312 191.408 63.912 ;
     RECT  191.408 2.148 191.512 127.452 ;
     RECT  191.512 2.418 191.704 127.182 ;
     RECT  191.704 63.312 193.813 63.912 ;
     RECT  193.813 62.64 194.101 63.912 ;
     RECT  194.101 62.64 194.316 62.664 ;
     RECT  194.101 62.664 194.364 62.736 ;
     RECT  194.101 62.736 194.316 62.76 ;
     RECT  194.101 62.76 194.364 62.832 ;
     RECT  194.101 62.832 194.316 62.856 ;
     RECT  194.101 62.856 194.364 62.928 ;
     RECT  194.101 62.928 194.316 62.952 ;
     RECT  194.101 62.952 194.364 63.024 ;
     RECT  194.101 63.024 194.316 63.048 ;
     RECT  194.101 63.048 194.364 63.12 ;
     RECT  194.101 63.12 194.316 63.144 ;
     RECT  194.101 63.144 194.364 63.216 ;
     RECT  194.101 63.216 194.316 63.24 ;
     RECT  194.101 63.24 194.364 63.312 ;
     RECT  194.101 63.312 194.316 63.336 ;
     RECT  194.101 63.336 194.364 63.408 ;
     RECT  194.101 63.408 194.316 63.432 ;
     RECT  194.101 63.432 194.364 63.504 ;
     RECT  194.101 63.504 194.316 63.528 ;
     RECT  194.101 63.528 194.364 63.6 ;
     RECT  194.101 63.6 194.316 63.624 ;
     RECT  194.101 63.624 194.364 63.696 ;
     RECT  194.101 63.696 194.316 63.72 ;
     RECT  194.101 63.72 194.364 63.792 ;
     RECT  194.101 63.792 194.316 63.816 ;
     RECT  194.101 63.816 194.364 63.888 ;
     RECT  194.101 63.888 194.316 63.912 ;
     RECT  194.101 63.912 194.364 63.984 ;
     RECT  194.101 63.984 194.316 64.008 ;
    LAYER M5 ;
     RECT  2.4 2.137 2.52 2.151 ;
     RECT  7.8 2.137 7.92 2.151 ;
     RECT  13.2 2.137 13.32 2.151 ;
     RECT  18.6 2.137 18.72 2.151 ;
     RECT  24 2.137 24.12 2.151 ;
     RECT  29.4 2.137 29.52 2.151 ;
     RECT  34.8 2.137 34.92 2.151 ;
     RECT  40.2 2.137 40.32 2.151 ;
     RECT  45.6 2.137 45.72 2.151 ;
     RECT  51 2.137 51.12 2.151 ;
     RECT  56.4 2.137 56.52 2.151 ;
     RECT  61.8 2.137 61.92 2.151 ;
     RECT  67.2 2.137 67.32 2.151 ;
     RECT  72.6 2.137 72.72 2.151 ;
     RECT  78 2.137 78.12 2.151 ;
     RECT  83.4 2.137 83.52 2.151 ;
     RECT  88.8 2.137 88.92 2.151 ;
     RECT  94.2 2.137 94.32 2.151 ;
     RECT  99.6 2.137 99.72 2.151 ;
     RECT  105 2.137 105.12 2.151 ;
     RECT  110.4 2.137 110.52 2.151 ;
     RECT  115.8 2.137 115.92 2.151 ;
     RECT  121.2 2.137 121.32 2.151 ;
     RECT  126.6 2.137 126.72 2.151 ;
     RECT  132 2.137 132.12 2.151 ;
     RECT  137.4 2.137 137.52 2.151 ;
     RECT  142.8 2.137 142.92 2.151 ;
     RECT  148.2 2.137 148.32 2.151 ;
     RECT  153.6 2.137 153.72 2.151 ;
     RECT  159 2.137 159.12 2.151 ;
     RECT  164.4 2.137 164.52 2.151 ;
     RECT  169.8 2.137 169.92 2.151 ;
     RECT  175.2 2.137 175.32 2.151 ;
     RECT  180.6 2.137 180.72 2.151 ;
     RECT  186 2.137 186.12 2.151 ;
     RECT  191.4 2.137 191.52 2.151 ;
     RECT  7.8 2.151 8.112 56.293 ;
     RECT  2.4 2.151 2.712 56.341 ;
     RECT  2.4 56.341 2.808 56.963 ;
     RECT  18.6 2.151 18.912 57.541 ;
     RECT  22.416 56.917 22.44 57.541 ;
     RECT  22.416 57.541 22.68 57.587 ;
     RECT  14.496 56.965 14.52 57.635 ;
     RECT  7.44 56.293 8.112 57.733 ;
     RECT  22.656 57.587 22.68 58.117 ;
     RECT  24 2.151 24.312 58.117 ;
     RECT  6.816 57.733 8.112 58.163 ;
     RECT  22.656 58.117 24.312 58.163 ;
     RECT  7.68 58.163 8.112 58.645 ;
     RECT  23.424 58.163 24.312 59.075 ;
     RECT  17.664 57.541 18.912 59.173 ;
     RECT  24 59.075 24.312 59.221 ;
     RECT  7.68 58.645 8.232 59.267 ;
     RECT  20.304 57.685 20.328 59.891 ;
     RECT  25.632 58.117 25.656 60.083 ;
     RECT  0.144 60.085 0.168 60.371 ;
     RECT  17.616 59.173 18.912 60.467 ;
     RECT  15.36 59.557 15.384 61.091 ;
     RECT  2.4 56.963 2.712 61.237 ;
     RECT  13.2 2.151 13.512 61.525 ;
     RECT  7.68 59.267 8.112 61.909 ;
     RECT  7.68 61.909 8.52 61.955 ;
     RECT  22.176 61.525 22.2 62.195 ;
     RECT  26.016 61.525 26.04 62.195 ;
     RECT  31.68 60.949 31.704 62.195 ;
     RECT  17.664 60.467 18.912 62.485 ;
     RECT  20.016 61.189 20.04 62.485 ;
     RECT  17.664 62.485 20.04 62.723 ;
     RECT  2.304 61.237 2.712 62.771 ;
     RECT  10.8 62.677 10.92 62.819 ;
     RECT  17.664 62.723 19.32 62.867 ;
     RECT  24 59.221 24.408 62.867 ;
     RECT  14.688 62.101 14.712 63.059 ;
     RECT  2.4 62.771 2.712 63.205 ;
     RECT  17.664 62.867 19.032 63.491 ;
     RECT  12.528 61.525 13.512 63.827 ;
     RECT  11.28 63.013 11.304 63.875 ;
     RECT  5.04 63.205 5.64 64.309 ;
     RECT  5.04 64.309 5.688 64.357 ;
     RECT  24 62.867 24.312 64.885 ;
     RECT  12.912 63.827 13.512 64.931 ;
     RECT  13.2 64.931 13.512 64.933 ;
     RECT  4.32 64.357 5.688 65.603 ;
     RECT  7.8 61.955 8.52 65.603 ;
     RECT  11.424 64.933 11.448 65.603 ;
     RECT  5.088 65.603 5.112 65.651 ;
     RECT  23.76 64.885 24.312 65.653 ;
     RECT  2.4 63.205 2.808 65.699 ;
     RECT  21.84 62.677 21.864 65.699 ;
     RECT  23.76 65.653 25.128 65.843 ;
     RECT  27.936 63.205 27.96 66.229 ;
     RECT  13.2 64.933 13.656 66.515 ;
     RECT  27.936 66.229 28.008 66.755 ;
     RECT  18.6 63.491 19.032 66.757 ;
     RECT  16.848 66.085 16.872 67.235 ;
     RECT  18.48 66.757 19.032 67.283 ;
     RECT  18.48 67.283 18.912 67.427 ;
     RECT  24 65.843 25.128 67.811 ;
     RECT  26.208 67.525 26.232 67.811 ;
     RECT  29.4 2.151 29.712 68.197 ;
     RECT  29.4 68.197 29.832 69.491 ;
     RECT  21.888 67.669 21.912 70.595 ;
     RECT  34.8 2.151 35.112 76.309 ;
     RECT  40.2 2.151 40.512 76.357 ;
     RECT  29.4 69.491 29.712 77.941 ;
     RECT  29.4 77.941 29.832 78.613 ;
     RECT  29.04 78.613 29.832 78.659 ;
     RECT  34.8 76.309 35.352 79.045 ;
     RECT  29.04 78.659 29.712 79.283 ;
     RECT  39.264 76.357 40.512 80.291 ;
     RECT  29.4 79.283 29.712 80.629 ;
     RECT  27.936 66.755 27.96 80.675 ;
     RECT  32.88 79.045 32.904 80.675 ;
     RECT  61.8 2.151 62.112 80.821 ;
     RECT  34.8 79.045 35.496 81.059 ;
     RECT  40.2 80.291 40.512 81.445 ;
     RECT  48.48 80.245 48.504 82.115 ;
     RECT  29.28 80.629 29.712 82.307 ;
     RECT  29.4 82.307 29.712 82.501 ;
     RECT  48.576 82.597 48.6 82.741 ;
     RECT  33.216 82.597 33.24 82.933 ;
     RECT  33.216 82.933 33.624 82.979 ;
     RECT  40.2 81.445 40.92 83.075 ;
     RECT  33.6 82.979 33.624 83.749 ;
     RECT  34.8 81.059 35.112 83.749 ;
     RECT  33.6 83.749 35.112 83.795 ;
     RECT  29.4 82.501 29.88 83.843 ;
     RECT  48.576 82.741 49.032 84.323 ;
     RECT  48.96 84.323 49.032 84.611 ;
     RECT  53.136 84.565 53.16 85.619 ;
     RECT  33.84 83.795 35.112 85.667 ;
     RECT  48.96 84.611 48.984 86.005 ;
     RECT  55.152 85.429 55.176 86.531 ;
     RECT  51 2.151 51.312 86.869 ;
     RECT  50.208 86.869 51.312 87.827 ;
     RECT  48.384 86.005 48.984 88.261 ;
     RECT  48.384 88.261 49.032 88.307 ;
     RECT  51 87.827 51.312 89.269 ;
     RECT  48.96 88.307 49.032 90.035 ;
     RECT  61.344 80.821 62.112 90.901 ;
     RECT  50.88 89.269 51.312 91.379 ;
     RECT  53.136 89.989 53.16 91.859 ;
     RECT  61.344 90.901 62.616 92.675 ;
     RECT  61.344 92.675 62.112 94.549 ;
     RECT  61.344 94.549 62.28 95.795 ;
     RECT  65.664 92.917 65.688 96.565 ;
     RECT  67.2 2.151 67.512 96.565 ;
     RECT  48.96 90.035 48.984 96.611 ;
     RECT  65.664 96.565 67.512 96.755 ;
     RECT  63.84 95.509 63.864 98.101 ;
     RECT  63.84 98.101 64.104 98.147 ;
     RECT  66.336 96.755 67.512 98.437 ;
     RECT  64.08 98.147 64.104 98.627 ;
     RECT  74.304 96.565 74.328 98.675 ;
     RECT  66.336 98.437 67.848 99.203 ;
     RECT  74.352 98.725 74.376 99.971 ;
     RECT  72.6 2.151 72.912 102.181 ;
     RECT  67.2 99.203 67.848 103.043 ;
     RECT  61.344 95.795 62.112 103.235 ;
     RECT  70.512 96.565 70.536 103.331 ;
     RECT  78 2.151 78.312 107.125 ;
     RECT  83.4 2.151 83.712 107.701 ;
     RECT  72.48 102.181 72.912 108.371 ;
     RECT  83.232 107.701 83.712 108.371 ;
     RECT  83.4 108.371 83.712 109.717 ;
     RECT  85.584 108.469 85.608 109.813 ;
     RECT  85.584 109.813 85.992 109.859 ;
     RECT  91.152 107.701 91.176 109.955 ;
     RECT  83.232 109.717 83.712 110.051 ;
     RECT  78 107.125 78.456 110.531 ;
     RECT  81.696 103.189 81.72 111.443 ;
     RECT  85.968 109.859 85.992 111.827 ;
     RECT  91.2 110.053 91.224 111.827 ;
     RECT  92.544 112.837 92.568 113.459 ;
     RECT  96 111.733 96.024 113.699 ;
     RECT  99.6 2.151 99.912 113.941 ;
     RECT  98.64 113.941 99.912 115.621 ;
     RECT  92.592 113.941 92.616 115.667 ;
     RECT  98.64 115.621 100.008 116.195 ;
     RECT  101.376 111.637 101.4 120.565 ;
     RECT  99.6 116.195 100.008 120.611 ;
     RECT  105 2.151 105.312 123.253 ;
     RECT  100.992 120.565 101.4 123.395 ;
     RECT  101.376 123.395 101.4 124.163 ;
     RECT  110.4 2.151 110.712 124.213 ;
     RECT  106.416 123.253 106.44 124.259 ;
     RECT  104.88 123.253 105.312 124.499 ;
     RECT  112.272 91.333 112.296 125.317 ;
     RECT  110.304 124.213 110.712 125.747 ;
     RECT  2.4 65.699 2.712 127.449 ;
     RECT  7.8 65.603 8.112 127.449 ;
     RECT  13.2 66.515 13.512 127.449 ;
     RECT  18.6 67.427 18.912 127.449 ;
     RECT  24 67.811 24.312 127.449 ;
     RECT  29.4 83.843 29.712 127.449 ;
     RECT  34.8 85.667 35.112 127.449 ;
     RECT  40.2 83.075 40.512 127.449 ;
     RECT  45.6 2.151 45.912 127.449 ;
     RECT  51 91.379 51.312 127.449 ;
     RECT  56.4 2.151 56.712 127.449 ;
     RECT  61.8 103.235 62.112 127.449 ;
     RECT  67.2 103.043 67.512 127.449 ;
     RECT  72.6 108.371 72.912 127.449 ;
     RECT  78 110.531 78.312 127.449 ;
     RECT  83.4 110.051 83.712 127.449 ;
     RECT  88.8 2.151 89.112 127.449 ;
     RECT  94.2 2.151 94.512 127.449 ;
     RECT  99.6 120.611 99.912 127.449 ;
     RECT  105 124.499 105.312 127.449 ;
     RECT  110.4 125.747 110.712 127.449 ;
     RECT  115.8 2.151 116.112 127.449 ;
     RECT  121.2 2.151 121.512 127.449 ;
     RECT  126.6 2.151 126.912 127.449 ;
     RECT  132 2.151 132.312 127.449 ;
     RECT  137.4 2.151 137.712 127.449 ;
     RECT  142.8 2.151 143.112 127.449 ;
     RECT  148.2 2.151 148.512 127.449 ;
     RECT  153.6 2.151 153.912 127.449 ;
     RECT  159 2.151 159.312 127.449 ;
     RECT  164.4 2.151 164.712 127.449 ;
     RECT  169.8 2.151 170.112 127.449 ;
     RECT  175.2 2.151 175.512 127.449 ;
     RECT  180.6 2.151 180.912 127.449 ;
     RECT  186 2.151 186.312 127.449 ;
     RECT  191.4 2.151 191.712 127.449 ;
     RECT  2.4 127.449 2.52 127.463 ;
     RECT  7.8 127.449 7.92 127.463 ;
     RECT  13.2 127.449 13.32 127.463 ;
     RECT  18.6 127.449 18.72 127.463 ;
     RECT  24 127.449 24.12 127.463 ;
     RECT  29.4 127.449 29.52 127.463 ;
     RECT  34.8 127.449 34.92 127.463 ;
     RECT  40.2 127.449 40.32 127.463 ;
     RECT  45.6 127.449 45.72 127.463 ;
     RECT  51 127.449 51.12 127.463 ;
     RECT  56.4 127.449 56.52 127.463 ;
     RECT  61.8 127.449 61.92 127.463 ;
     RECT  67.2 127.449 67.32 127.463 ;
     RECT  72.6 127.449 72.72 127.463 ;
     RECT  78 127.449 78.12 127.463 ;
     RECT  83.4 127.449 83.52 127.463 ;
     RECT  88.8 127.449 88.92 127.463 ;
     RECT  94.2 127.449 94.32 127.463 ;
     RECT  99.6 127.449 99.72 127.463 ;
     RECT  105 127.449 105.12 127.463 ;
     RECT  110.4 127.449 110.52 127.463 ;
     RECT  115.8 127.449 115.92 127.463 ;
     RECT  121.2 127.449 121.32 127.463 ;
     RECT  126.6 127.449 126.72 127.463 ;
     RECT  132 127.449 132.12 127.463 ;
     RECT  137.4 127.449 137.52 127.463 ;
     RECT  142.8 127.449 142.92 127.463 ;
     RECT  148.2 127.449 148.32 127.463 ;
     RECT  153.6 127.449 153.72 127.463 ;
     RECT  159 127.449 159.12 127.463 ;
     RECT  164.4 127.449 164.52 127.463 ;
     RECT  169.8 127.449 169.92 127.463 ;
     RECT  175.2 127.449 175.32 127.463 ;
     RECT  180.6 127.449 180.72 127.463 ;
     RECT  186 127.449 186.12 127.463 ;
     RECT  191.4 127.449 191.52 127.463 ;
     RECT  112.272 125.317 113.064 127.573 ;
     RECT  112.272 127.573 113.256 129.397 ;
     RECT  112.272 129.397 113.352 129.516 ;
     RECT  112.296 129.516 112.368 129.552 ;
     RECT  112.392 129.516 112.464 129.552 ;
     RECT  112.488 129.516 112.56 129.552 ;
     RECT  112.584 129.516 112.656 129.552 ;
     RECT  112.68 129.516 112.752 129.552 ;
     RECT  112.776 129.516 112.848 129.552 ;
     RECT  112.872 129.516 112.944 129.552 ;
     RECT  112.968 129.516 113.04 129.552 ;
     RECT  113.064 129.516 113.136 129.552 ;
     RECT  113.16 129.516 113.232 129.552 ;
     RECT  113.256 129.516 113.328 129.552 ;
     RECT  13.512 56.965 14.496 57.635 ;
     RECT  22.68 57.541 24 58.117 ;
     RECT  18.912 57.685 20.304 59.891 ;
     RECT  24.312 58.117 25.632 59.221 ;
     RECT  24.408 59.221 25.632 60.083 ;
     RECT  18.912 59.891 20.04 61.189 ;
     RECT  18.912 61.189 20.016 62.485 ;
     RECT  13.512 62.101 14.688 63.059 ;
     RECT  11.304 63.013 12.528 63.827 ;
     RECT  27.96 63.205 29.4 66.229 ;
     RECT  11.304 63.827 12.912 63.875 ;
     RECT  11.424 63.875 12.912 64.931 ;
     RECT  2.808 64.357 4.32 65.603 ;
     RECT  11.424 64.931 11.448 64.933 ;
     RECT  28.008 66.229 29.4 66.755 ;
     RECT  27.96 66.755 29.4 78.613 ;
     RECT  25.128 67.525 26.208 67.811 ;
     RECT  27.96 78.613 29.04 79.283 ;
     RECT  27.96 79.283 29.4 80.629 ;
     RECT  27.96 80.629 29.28 80.675 ;
     RECT  33.624 82.933 34.8 83.749 ;
     RECT  55.176 85.429 56.4 86.531 ;
     RECT  48.984 86.869 50.208 87.827 ;
     RECT  48.984 87.827 49.032 88.261 ;
     RECT  50.88 87.827 51 89.269 ;
     RECT  65.688 92.917 67.2 96.565 ;
     RECT  72.912 96.565 74.304 98.675 ;
     RECT  72.912 98.675 74.328 98.725 ;
     RECT  72.912 98.725 74.352 99.971 ;
     RECT  81.72 107.701 83.232 108.371 ;
     RECT  81.72 108.371 83.4 109.717 ;
     RECT  81.72 109.717 83.232 110.051 ;
     RECT  99.912 111.637 101.376 115.621 ;
     RECT  94.512 111.733 96 113.699 ;
     RECT  100.008 115.621 101.376 120.565 ;
     RECT  100.008 120.565 100.992 120.611 ;
     RECT  99.912 120.611 100.992 123.395 ;
     RECT  105.312 123.253 106.416 124.259 ;
     RECT  99.912 123.395 101.376 124.163 ;
  END
END dsfd_vm_xio_request
END LIBRARY
